VERSION 5.8 ;
BUSBITCHARS "[]" ;
DIVIDERCHAR "/" ;
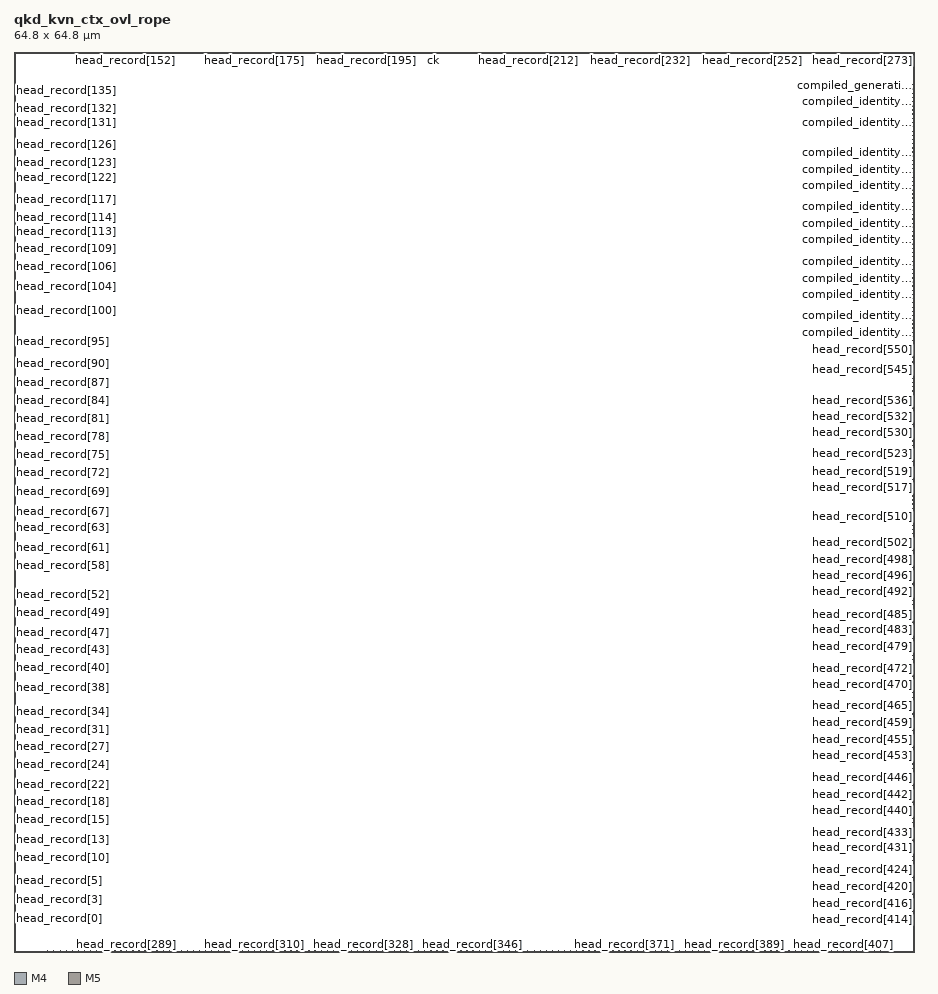
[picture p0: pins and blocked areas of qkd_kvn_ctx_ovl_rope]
MACRO qkd_kvn_ctx_ovl_rope
  CLASS BLOCK ;
  ORIGIN 0 0 ;
  SIZE 64.800000 BY 64.800000 ;
  SYMMETRY X Y ;
  PIN head_record[0]
    DIRECTION INPUT ;
    USE SIGNAL ;
    PORT
      LAYER M4 ;
      RECT 0.000000 2.400000 0.084000 2.424000 ;
    END
  END head_record[0]
  PIN head_record[1]
    DIRECTION INPUT ;
    USE SIGNAL ;
    PORT
      LAYER M4 ;
      RECT 0.000000 2.832000 0.084000 2.856000 ;
    END
  END head_record[1]
  PIN head_record[2]
    DIRECTION INPUT ;
    USE SIGNAL ;
    PORT
      LAYER M4 ;
      RECT 0.000000 3.312000 0.084000 3.336000 ;
    END
  END head_record[2]
  PIN head_record[3]
    DIRECTION INPUT ;
    USE SIGNAL ;
    PORT
      LAYER M4 ;
      RECT 0.000000 3.744000 0.084000 3.768000 ;
    END
  END head_record[3]
  PIN head_record[4]
    DIRECTION INPUT ;
    USE SIGNAL ;
    PORT
      LAYER M4 ;
      RECT 0.000000 4.176000 0.084000 4.200000 ;
    END
  END head_record[4]
  PIN head_record[5]
    DIRECTION INPUT ;
    USE SIGNAL ;
    PORT
      LAYER M4 ;
      RECT 0.000000 4.608000 0.084000 4.632000 ;
    END
  END head_record[5]
  PIN head_record[6]
    DIRECTION INPUT ;
    USE SIGNAL ;
    PORT
      LAYER M4 ;
      RECT 0.000000 5.040000 0.084000 5.064000 ;
    END
  END head_record[6]
  PIN head_record[7]
    DIRECTION INPUT ;
    USE SIGNAL ;
    PORT
      LAYER M4 ;
      RECT 0.000000 5.472000 0.084000 5.496000 ;
    END
  END head_record[7]
  PIN head_record[8]
    DIRECTION INPUT ;
    USE SIGNAL ;
    PORT
      LAYER M4 ;
      RECT 0.000000 5.904000 0.084000 5.928000 ;
    END
  END head_record[8]
  PIN head_record[9]
    DIRECTION INPUT ;
    USE SIGNAL ;
    PORT
      LAYER M4 ;
      RECT 0.000000 6.336000 0.084000 6.360000 ;
    END
  END head_record[9]
  PIN head_record[10]
    DIRECTION INPUT ;
    USE SIGNAL ;
    PORT
      LAYER M4 ;
      RECT 0.000000 6.768000 0.084000 6.792000 ;
    END
  END head_record[10]
  PIN head_record[11]
    DIRECTION INPUT ;
    USE SIGNAL ;
    PORT
      LAYER M4 ;
      RECT 0.000000 7.248000 0.084000 7.272000 ;
    END
  END head_record[11]
  PIN head_record[12]
    DIRECTION INPUT ;
    USE SIGNAL ;
    PORT
      LAYER M4 ;
      RECT 0.000000 7.680000 0.084000 7.704000 ;
    END
  END head_record[12]
  PIN head_record[13]
    DIRECTION INPUT ;
    USE SIGNAL ;
    PORT
      LAYER M4 ;
      RECT 0.000000 8.112000 0.084000 8.136000 ;
    END
  END head_record[13]
  PIN head_record[14]
    DIRECTION INPUT ;
    USE SIGNAL ;
    PORT
      LAYER M4 ;
      RECT 0.000000 8.544000 0.084000 8.568000 ;
    END
  END head_record[14]
  PIN head_record[15]
    DIRECTION INPUT ;
    USE SIGNAL ;
    PORT
      LAYER M4 ;
      RECT 0.000000 8.976000 0.084000 9.000000 ;
    END
  END head_record[15]
  PIN head_record[16]
    DIRECTION INPUT ;
    USE SIGNAL ;
    PORT
      LAYER M4 ;
      RECT 0.000000 9.408000 0.084000 9.432000 ;
    END
  END head_record[16]
  PIN head_record[17]
    DIRECTION INPUT ;
    USE SIGNAL ;
    PORT
      LAYER M4 ;
      RECT 0.000000 9.840000 0.084000 9.864000 ;
    END
  END head_record[17]
  PIN head_record[18]
    DIRECTION INPUT ;
    USE SIGNAL ;
    PORT
      LAYER M4 ;
      RECT 0.000000 10.272000 0.084000 10.296000 ;
    END
  END head_record[18]
  PIN head_record[19]
    DIRECTION INPUT ;
    USE SIGNAL ;
    PORT
      LAYER M4 ;
      RECT 0.000000 10.752000 0.084000 10.776000 ;
    END
  END head_record[19]
  PIN head_record[20]
    DIRECTION INPUT ;
    USE SIGNAL ;
    PORT
      LAYER M4 ;
      RECT 0.000000 11.184000 0.084000 11.208000 ;
    END
  END head_record[20]
  PIN head_record[21]
    DIRECTION INPUT ;
    USE SIGNAL ;
    PORT
      LAYER M4 ;
      RECT 0.000000 11.616000 0.084000 11.640000 ;
    END
  END head_record[21]
  PIN head_record[22]
    DIRECTION INPUT ;
    USE SIGNAL ;
    PORT
      LAYER M4 ;
      RECT 0.000000 12.048000 0.084000 12.072000 ;
    END
  END head_record[22]
  PIN head_record[23]
    DIRECTION INPUT ;
    USE SIGNAL ;
    PORT
      LAYER M4 ;
      RECT 0.000000 12.480000 0.084000 12.504000 ;
    END
  END head_record[23]
  PIN head_record[24]
    DIRECTION INPUT ;
    USE SIGNAL ;
    PORT
      LAYER M4 ;
      RECT 0.000000 12.912000 0.084000 12.936000 ;
    END
  END head_record[24]
  PIN head_record[25]
    DIRECTION INPUT ;
    USE SIGNAL ;
    PORT
      LAYER M4 ;
      RECT 0.000000 13.344000 0.084000 13.368000 ;
    END
  END head_record[25]
  PIN head_record[26]
    DIRECTION INPUT ;
    USE SIGNAL ;
    PORT
      LAYER M4 ;
      RECT 0.000000 13.776000 0.084000 13.800000 ;
    END
  END head_record[26]
  PIN head_record[27]
    DIRECTION INPUT ;
    USE SIGNAL ;
    PORT
      LAYER M4 ;
      RECT 0.000000 14.208000 0.084000 14.232000 ;
    END
  END head_record[27]
  PIN head_record[28]
    DIRECTION INPUT ;
    USE SIGNAL ;
    PORT
      LAYER M4 ;
      RECT 0.000000 14.688000 0.084000 14.712000 ;
    END
  END head_record[28]
  PIN head_record[29]
    DIRECTION INPUT ;
    USE SIGNAL ;
    PORT
      LAYER M4 ;
      RECT 0.000000 15.120000 0.084000 15.144000 ;
    END
  END head_record[29]
  PIN head_record[30]
    DIRECTION INPUT ;
    USE SIGNAL ;
    PORT
      LAYER M4 ;
      RECT 0.000000 15.552000 0.084000 15.576000 ;
    END
  END head_record[30]
  PIN head_record[31]
    DIRECTION INPUT ;
    USE SIGNAL ;
    PORT
      LAYER M4 ;
      RECT 0.000000 15.984000 0.084000 16.008000 ;
    END
  END head_record[31]
  PIN head_record[32]
    DIRECTION INPUT ;
    USE SIGNAL ;
    PORT
      LAYER M4 ;
      RECT 0.000000 16.416000 0.084000 16.440000 ;
    END
  END head_record[32]
  PIN head_record[33]
    DIRECTION INPUT ;
    USE SIGNAL ;
    PORT
      LAYER M4 ;
      RECT 0.000000 16.848000 0.084000 16.872000 ;
    END
  END head_record[33]
  PIN head_record[34]
    DIRECTION INPUT ;
    USE SIGNAL ;
    PORT
      LAYER M4 ;
      RECT 0.000000 17.280000 0.084000 17.304000 ;
    END
  END head_record[34]
  PIN head_record[35]
    DIRECTION INPUT ;
    USE SIGNAL ;
    PORT
      LAYER M4 ;
      RECT 0.000000 17.712000 0.084000 17.736000 ;
    END
  END head_record[35]
  PIN head_record[36]
    DIRECTION INPUT ;
    USE SIGNAL ;
    PORT
      LAYER M4 ;
      RECT 0.000000 18.144000 0.084000 18.168000 ;
    END
  END head_record[36]
  PIN head_record[37]
    DIRECTION INPUT ;
    USE SIGNAL ;
    PORT
      LAYER M4 ;
      RECT 0.000000 18.624000 0.084000 18.648000 ;
    END
  END head_record[37]
  PIN head_record[38]
    DIRECTION INPUT ;
    USE SIGNAL ;
    PORT
      LAYER M4 ;
      RECT 0.000000 19.056000 0.084000 19.080000 ;
    END
  END head_record[38]
  PIN head_record[39]
    DIRECTION INPUT ;
    USE SIGNAL ;
    PORT
      LAYER M4 ;
      RECT 0.000000 19.488000 0.084000 19.512000 ;
    END
  END head_record[39]
  PIN head_record[40]
    DIRECTION INPUT ;
    USE SIGNAL ;
    PORT
      LAYER M4 ;
      RECT 0.000000 19.920000 0.084000 19.944000 ;
    END
  END head_record[40]
  PIN head_record[41]
    DIRECTION INPUT ;
    USE SIGNAL ;
    PORT
      LAYER M4 ;
      RECT 0.000000 20.352000 0.084000 20.376000 ;
    END
  END head_record[41]
  PIN head_record[42]
    DIRECTION INPUT ;
    USE SIGNAL ;
    PORT
      LAYER M4 ;
      RECT 0.000000 20.784000 0.084000 20.808000 ;
    END
  END head_record[42]
  PIN head_record[43]
    DIRECTION INPUT ;
    USE SIGNAL ;
    PORT
      LAYER M4 ;
      RECT 0.000000 21.216000 0.084000 21.240000 ;
    END
  END head_record[43]
  PIN head_record[44]
    DIRECTION INPUT ;
    USE SIGNAL ;
    PORT
      LAYER M4 ;
      RECT 0.000000 21.648000 0.084000 21.672000 ;
    END
  END head_record[44]
  PIN head_record[45]
    DIRECTION INPUT ;
    USE SIGNAL ;
    PORT
      LAYER M4 ;
      RECT 0.000000 22.128000 0.084000 22.152000 ;
    END
  END head_record[45]
  PIN head_record[46]
    DIRECTION INPUT ;
    USE SIGNAL ;
    PORT
      LAYER M4 ;
      RECT 0.000000 22.560000 0.084000 22.584000 ;
    END
  END head_record[46]
  PIN head_record[47]
    DIRECTION INPUT ;
    USE SIGNAL ;
    PORT
      LAYER M4 ;
      RECT 0.000000 22.992000 0.084000 23.016000 ;
    END
  END head_record[47]
  PIN head_record[48]
    DIRECTION INPUT ;
    USE SIGNAL ;
    PORT
      LAYER M4 ;
      RECT 0.000000 23.424000 0.084000 23.448000 ;
    END
  END head_record[48]
  PIN head_record[49]
    DIRECTION INPUT ;
    USE SIGNAL ;
    PORT
      LAYER M4 ;
      RECT 0.000000 23.856000 0.084000 23.880000 ;
    END
  END head_record[49]
  PIN head_record[50]
    DIRECTION INPUT ;
    USE SIGNAL ;
    PORT
      LAYER M4 ;
      RECT 0.000000 24.288000 0.084000 24.312000 ;
    END
  END head_record[50]
  PIN head_record[51]
    DIRECTION INPUT ;
    USE SIGNAL ;
    PORT
      LAYER M4 ;
      RECT 0.000000 24.720000 0.084000 24.744000 ;
    END
  END head_record[51]
  PIN head_record[52]
    DIRECTION INPUT ;
    USE SIGNAL ;
    PORT
      LAYER M4 ;
      RECT 0.000000 25.152000 0.084000 25.176000 ;
    END
  END head_record[52]
  PIN head_record[53]
    DIRECTION INPUT ;
    USE SIGNAL ;
    PORT
      LAYER M4 ;
      RECT 0.000000 25.584000 0.084000 25.608000 ;
    END
  END head_record[53]
  PIN head_record[54]
    DIRECTION INPUT ;
    USE SIGNAL ;
    PORT
      LAYER M4 ;
      RECT 0.000000 26.064000 0.084000 26.088000 ;
    END
  END head_record[54]
  PIN head_record[55]
    DIRECTION INPUT ;
    USE SIGNAL ;
    PORT
      LAYER M4 ;
      RECT 0.000000 26.496000 0.084000 26.520000 ;
    END
  END head_record[55]
  PIN head_record[56]
    DIRECTION INPUT ;
    USE SIGNAL ;
    PORT
      LAYER M4 ;
      RECT 0.000000 26.928000 0.084000 26.952000 ;
    END
  END head_record[56]
  PIN head_record[57]
    DIRECTION INPUT ;
    USE SIGNAL ;
    PORT
      LAYER M4 ;
      RECT 0.000000 27.360000 0.084000 27.384000 ;
    END
  END head_record[57]
  PIN head_record[58]
    DIRECTION INPUT ;
    USE SIGNAL ;
    PORT
      LAYER M4 ;
      RECT 0.000000 27.792000 0.084000 27.816000 ;
    END
  END head_record[58]
  PIN head_record[59]
    DIRECTION INPUT ;
    USE SIGNAL ;
    PORT
      LAYER M4 ;
      RECT 0.000000 28.224000 0.084000 28.248000 ;
    END
  END head_record[59]
  PIN head_record[60]
    DIRECTION INPUT ;
    USE SIGNAL ;
    PORT
      LAYER M4 ;
      RECT 0.000000 28.656000 0.084000 28.680000 ;
    END
  END head_record[60]
  PIN head_record[61]
    DIRECTION INPUT ;
    USE SIGNAL ;
    PORT
      LAYER M4 ;
      RECT 0.000000 29.088000 0.084000 29.112000 ;
    END
  END head_record[61]
  PIN head_record[62]
    DIRECTION INPUT ;
    USE SIGNAL ;
    PORT
      LAYER M4 ;
      RECT 0.000000 29.520000 0.084000 29.544000 ;
    END
  END head_record[62]
  PIN head_record[63]
    DIRECTION INPUT ;
    USE SIGNAL ;
    PORT
      LAYER M4 ;
      RECT 0.000000 30.000000 0.084000 30.024000 ;
    END
  END head_record[63]
  PIN head_record[64]
    DIRECTION INPUT ;
    USE SIGNAL ;
    PORT
      LAYER M4 ;
      RECT 0.000000 30.432000 0.084000 30.456000 ;
    END
  END head_record[64]
  PIN head_record[65]
    DIRECTION INPUT ;
    USE SIGNAL ;
    PORT
      LAYER M4 ;
      RECT 0.000000 30.864000 0.084000 30.888000 ;
    END
  END head_record[65]
  PIN head_record[66]
    DIRECTION INPUT ;
    USE SIGNAL ;
    PORT
      LAYER M4 ;
      RECT 0.000000 31.296000 0.084000 31.320000 ;
    END
  END head_record[66]
  PIN head_record[67]
    DIRECTION INPUT ;
    USE SIGNAL ;
    PORT
      LAYER M4 ;
      RECT 0.000000 31.728000 0.084000 31.752000 ;
    END
  END head_record[67]
  PIN head_record[68]
    DIRECTION INPUT ;
    USE SIGNAL ;
    PORT
      LAYER M4 ;
      RECT 0.000000 32.160000 0.084000 32.184000 ;
    END
  END head_record[68]
  PIN head_record[69]
    DIRECTION INPUT ;
    USE SIGNAL ;
    PORT
      LAYER M4 ;
      RECT 0.000000 32.592000 0.084000 32.616000 ;
    END
  END head_record[69]
  PIN head_record[70]
    DIRECTION INPUT ;
    USE SIGNAL ;
    PORT
      LAYER M4 ;
      RECT 0.000000 33.024000 0.084000 33.048000 ;
    END
  END head_record[70]
  PIN head_record[71]
    DIRECTION INPUT ;
    USE SIGNAL ;
    PORT
      LAYER M4 ;
      RECT 0.000000 33.504000 0.084000 33.528000 ;
    END
  END head_record[71]
  PIN head_record[72]
    DIRECTION INPUT ;
    USE SIGNAL ;
    PORT
      LAYER M4 ;
      RECT 0.000000 33.936000 0.084000 33.960000 ;
    END
  END head_record[72]
  PIN head_record[73]
    DIRECTION INPUT ;
    USE SIGNAL ;
    PORT
      LAYER M4 ;
      RECT 0.000000 34.368000 0.084000 34.392000 ;
    END
  END head_record[73]
  PIN head_record[74]
    DIRECTION INPUT ;
    USE SIGNAL ;
    PORT
      LAYER M4 ;
      RECT 0.000000 34.800000 0.084000 34.824000 ;
    END
  END head_record[74]
  PIN head_record[75]
    DIRECTION INPUT ;
    USE SIGNAL ;
    PORT
      LAYER M4 ;
      RECT 0.000000 35.232000 0.084000 35.256000 ;
    END
  END head_record[75]
  PIN head_record[76]
    DIRECTION INPUT ;
    USE SIGNAL ;
    PORT
      LAYER M4 ;
      RECT 0.000000 35.664000 0.084000 35.688000 ;
    END
  END head_record[76]
  PIN head_record[77]
    DIRECTION INPUT ;
    USE SIGNAL ;
    PORT
      LAYER M4 ;
      RECT 0.000000 36.096000 0.084000 36.120000 ;
    END
  END head_record[77]
  PIN head_record[78]
    DIRECTION INPUT ;
    USE SIGNAL ;
    PORT
      LAYER M4 ;
      RECT 0.000000 36.528000 0.084000 36.552000 ;
    END
  END head_record[78]
  PIN head_record[79]
    DIRECTION INPUT ;
    USE SIGNAL ;
    PORT
      LAYER M4 ;
      RECT 0.000000 36.960000 0.084000 36.984000 ;
    END
  END head_record[79]
  PIN head_record[80]
    DIRECTION INPUT ;
    USE SIGNAL ;
    PORT
      LAYER M4 ;
      RECT 0.000000 37.440000 0.084000 37.464000 ;
    END
  END head_record[80]
  PIN head_record[81]
    DIRECTION INPUT ;
    USE SIGNAL ;
    PORT
      LAYER M4 ;
      RECT 0.000000 37.872000 0.084000 37.896000 ;
    END
  END head_record[81]
  PIN head_record[82]
    DIRECTION INPUT ;
    USE SIGNAL ;
    PORT
      LAYER M4 ;
      RECT 0.000000 38.304000 0.084000 38.328000 ;
    END
  END head_record[82]
  PIN head_record[83]
    DIRECTION INPUT ;
    USE SIGNAL ;
    PORT
      LAYER M4 ;
      RECT 0.000000 38.736000 0.084000 38.760000 ;
    END
  END head_record[83]
  PIN head_record[84]
    DIRECTION INPUT ;
    USE SIGNAL ;
    PORT
      LAYER M4 ;
      RECT 0.000000 39.168000 0.084000 39.192000 ;
    END
  END head_record[84]
  PIN head_record[85]
    DIRECTION INPUT ;
    USE SIGNAL ;
    PORT
      LAYER M4 ;
      RECT 0.000000 39.600000 0.084000 39.624000 ;
    END
  END head_record[85]
  PIN head_record[86]
    DIRECTION INPUT ;
    USE SIGNAL ;
    PORT
      LAYER M4 ;
      RECT 0.000000 40.032000 0.084000 40.056000 ;
    END
  END head_record[86]
  PIN head_record[87]
    DIRECTION INPUT ;
    USE SIGNAL ;
    PORT
      LAYER M4 ;
      RECT 0.000000 40.464000 0.084000 40.488000 ;
    END
  END head_record[87]
  PIN head_record[88]
    DIRECTION INPUT ;
    USE SIGNAL ;
    PORT
      LAYER M4 ;
      RECT 0.000000 40.944000 0.084000 40.968000 ;
    END
  END head_record[88]
  PIN head_record[89]
    DIRECTION INPUT ;
    USE SIGNAL ;
    PORT
      LAYER M4 ;
      RECT 0.000000 41.376000 0.084000 41.400000 ;
    END
  END head_record[89]
  PIN head_record[90]
    DIRECTION INPUT ;
    USE SIGNAL ;
    PORT
      LAYER M4 ;
      RECT 0.000000 41.808000 0.084000 41.832000 ;
    END
  END head_record[90]
  PIN head_record[91]
    DIRECTION INPUT ;
    USE SIGNAL ;
    PORT
      LAYER M4 ;
      RECT 0.000000 42.240000 0.084000 42.264000 ;
    END
  END head_record[91]
  PIN head_record[92]
    DIRECTION INPUT ;
    USE SIGNAL ;
    PORT
      LAYER M4 ;
      RECT 0.000000 42.672000 0.084000 42.696000 ;
    END
  END head_record[92]
  PIN head_record[93]
    DIRECTION INPUT ;
    USE SIGNAL ;
    PORT
      LAYER M4 ;
      RECT 0.000000 43.104000 0.084000 43.128000 ;
    END
  END head_record[93]
  PIN head_record[94]
    DIRECTION INPUT ;
    USE SIGNAL ;
    PORT
      LAYER M4 ;
      RECT 0.000000 43.536000 0.084000 43.560000 ;
    END
  END head_record[94]
  PIN head_record[95]
    DIRECTION INPUT ;
    USE SIGNAL ;
    PORT
      LAYER M4 ;
      RECT 0.000000 43.968000 0.084000 43.992000 ;
    END
  END head_record[95]
  PIN head_record[96]
    DIRECTION INPUT ;
    USE SIGNAL ;
    PORT
      LAYER M4 ;
      RECT 0.000000 44.400000 0.084000 44.424000 ;
    END
  END head_record[96]
  PIN head_record[97]
    DIRECTION INPUT ;
    USE SIGNAL ;
    PORT
      LAYER M4 ;
      RECT 0.000000 44.880000 0.084000 44.904000 ;
    END
  END head_record[97]
  PIN head_record[98]
    DIRECTION INPUT ;
    USE SIGNAL ;
    PORT
      LAYER M4 ;
      RECT 0.000000 45.312000 0.084000 45.336000 ;
    END
  END head_record[98]
  PIN head_record[99]
    DIRECTION INPUT ;
    USE SIGNAL ;
    PORT
      LAYER M4 ;
      RECT 0.000000 45.744000 0.084000 45.768000 ;
    END
  END head_record[99]
  PIN head_record[100]
    DIRECTION INPUT ;
    USE SIGNAL ;
    PORT
      LAYER M4 ;
      RECT 0.000000 46.176000 0.084000 46.200000 ;
    END
  END head_record[100]
  PIN head_record[101]
    DIRECTION INPUT ;
    USE SIGNAL ;
    PORT
      LAYER M4 ;
      RECT 0.000000 46.608000 0.084000 46.632000 ;
    END
  END head_record[101]
  PIN head_record[102]
    DIRECTION INPUT ;
    USE SIGNAL ;
    PORT
      LAYER M4 ;
      RECT 0.000000 47.040000 0.084000 47.064000 ;
    END
  END head_record[102]
  PIN head_record[103]
    DIRECTION INPUT ;
    USE SIGNAL ;
    PORT
      LAYER M4 ;
      RECT 0.000000 47.472000 0.084000 47.496000 ;
    END
  END head_record[103]
  PIN head_record[104]
    DIRECTION INPUT ;
    USE SIGNAL ;
    PORT
      LAYER M4 ;
      RECT 0.000000 47.904000 0.084000 47.928000 ;
    END
  END head_record[104]
  PIN head_record[105]
    DIRECTION INPUT ;
    USE SIGNAL ;
    PORT
      LAYER M4 ;
      RECT 0.000000 48.336000 0.084000 48.360000 ;
    END
  END head_record[105]
  PIN head_record[106]
    DIRECTION INPUT ;
    USE SIGNAL ;
    PORT
      LAYER M4 ;
      RECT 0.000000 48.816000 0.084000 48.840000 ;
    END
  END head_record[106]
  PIN head_record[107]
    DIRECTION INPUT ;
    USE SIGNAL ;
    PORT
      LAYER M4 ;
      RECT 0.000000 49.248000 0.084000 49.272000 ;
    END
  END head_record[107]
  PIN head_record[108]
    DIRECTION INPUT ;
    USE SIGNAL ;
    PORT
      LAYER M4 ;
      RECT 0.000000 49.680000 0.084000 49.704000 ;
    END
  END head_record[108]
  PIN head_record[109]
    DIRECTION INPUT ;
    USE SIGNAL ;
    PORT
      LAYER M4 ;
      RECT 0.000000 50.112000 0.084000 50.136000 ;
    END
  END head_record[109]
  PIN head_record[110]
    DIRECTION INPUT ;
    USE SIGNAL ;
    PORT
      LAYER M4 ;
      RECT 0.000000 50.544000 0.084000 50.568000 ;
    END
  END head_record[110]
  PIN head_record[111]
    DIRECTION INPUT ;
    USE SIGNAL ;
    PORT
      LAYER M4 ;
      RECT 0.000000 50.976000 0.084000 51.000000 ;
    END
  END head_record[111]
  PIN head_record[112]
    DIRECTION INPUT ;
    USE SIGNAL ;
    PORT
      LAYER M4 ;
      RECT 0.000000 51.408000 0.084000 51.432000 ;
    END
  END head_record[112]
  PIN head_record[113]
    DIRECTION INPUT ;
    USE SIGNAL ;
    PORT
      LAYER M4 ;
      RECT 0.000000 51.840000 0.084000 51.864000 ;
    END
  END head_record[113]
  PIN head_record[114]
    DIRECTION INPUT ;
    USE SIGNAL ;
    PORT
      LAYER M4 ;
      RECT 0.000000 52.320000 0.084000 52.344000 ;
    END
  END head_record[114]
  PIN head_record[115]
    DIRECTION INPUT ;
    USE SIGNAL ;
    PORT
      LAYER M4 ;
      RECT 0.000000 52.752000 0.084000 52.776000 ;
    END
  END head_record[115]
  PIN head_record[116]
    DIRECTION INPUT ;
    USE SIGNAL ;
    PORT
      LAYER M4 ;
      RECT 0.000000 53.184000 0.084000 53.208000 ;
    END
  END head_record[116]
  PIN head_record[117]
    DIRECTION INPUT ;
    USE SIGNAL ;
    PORT
      LAYER M4 ;
      RECT 0.000000 53.616000 0.084000 53.640000 ;
    END
  END head_record[117]
  PIN head_record[118]
    DIRECTION INPUT ;
    USE SIGNAL ;
    PORT
      LAYER M4 ;
      RECT 0.000000 54.048000 0.084000 54.072000 ;
    END
  END head_record[118]
  PIN head_record[119]
    DIRECTION INPUT ;
    USE SIGNAL ;
    PORT
      LAYER M4 ;
      RECT 0.000000 54.480000 0.084000 54.504000 ;
    END
  END head_record[119]
  PIN head_record[120]
    DIRECTION INPUT ;
    USE SIGNAL ;
    PORT
      LAYER M4 ;
      RECT 0.000000 54.912000 0.084000 54.936000 ;
    END
  END head_record[120]
  PIN head_record[121]
    DIRECTION INPUT ;
    USE SIGNAL ;
    PORT
      LAYER M4 ;
      RECT 0.000000 55.344000 0.084000 55.368000 ;
    END
  END head_record[121]
  PIN head_record[122]
    DIRECTION INPUT ;
    USE SIGNAL ;
    PORT
      LAYER M4 ;
      RECT 0.000000 55.776000 0.084000 55.800000 ;
    END
  END head_record[122]
  PIN head_record[123]
    DIRECTION INPUT ;
    USE SIGNAL ;
    PORT
      LAYER M4 ;
      RECT 0.000000 56.256000 0.084000 56.280000 ;
    END
  END head_record[123]
  PIN head_record[124]
    DIRECTION INPUT ;
    USE SIGNAL ;
    PORT
      LAYER M4 ;
      RECT 0.000000 56.688000 0.084000 56.712000 ;
    END
  END head_record[124]
  PIN head_record[125]
    DIRECTION INPUT ;
    USE SIGNAL ;
    PORT
      LAYER M4 ;
      RECT 0.000000 57.120000 0.084000 57.144000 ;
    END
  END head_record[125]
  PIN head_record[126]
    DIRECTION INPUT ;
    USE SIGNAL ;
    PORT
      LAYER M4 ;
      RECT 0.000000 57.552000 0.084000 57.576000 ;
    END
  END head_record[126]
  PIN head_record[127]
    DIRECTION INPUT ;
    USE SIGNAL ;
    PORT
      LAYER M4 ;
      RECT 0.000000 57.984000 0.084000 58.008000 ;
    END
  END head_record[127]
  PIN head_record[128]
    DIRECTION INPUT ;
    USE SIGNAL ;
    PORT
      LAYER M4 ;
      RECT 0.000000 58.416000 0.084000 58.440000 ;
    END
  END head_record[128]
  PIN head_record[129]
    DIRECTION INPUT ;
    USE SIGNAL ;
    PORT
      LAYER M4 ;
      RECT 0.000000 58.848000 0.084000 58.872000 ;
    END
  END head_record[129]
  PIN head_record[130]
    DIRECTION INPUT ;
    USE SIGNAL ;
    PORT
      LAYER M4 ;
      RECT 0.000000 59.280000 0.084000 59.304000 ;
    END
  END head_record[130]
  PIN head_record[131]
    DIRECTION INPUT ;
    USE SIGNAL ;
    PORT
      LAYER M4 ;
      RECT 0.000000 59.712000 0.084000 59.736000 ;
    END
  END head_record[131]
  PIN head_record[132]
    DIRECTION INPUT ;
    USE SIGNAL ;
    PORT
      LAYER M4 ;
      RECT 0.000000 60.192000 0.084000 60.216000 ;
    END
  END head_record[132]
  PIN head_record[133]
    DIRECTION INPUT ;
    USE SIGNAL ;
    PORT
      LAYER M4 ;
      RECT 0.000000 60.624000 0.084000 60.648000 ;
    END
  END head_record[133]
  PIN head_record[134]
    DIRECTION INPUT ;
    USE SIGNAL ;
    PORT
      LAYER M4 ;
      RECT 0.000000 61.056000 0.084000 61.080000 ;
    END
  END head_record[134]
  PIN head_record[135]
    DIRECTION INPUT ;
    USE SIGNAL ;
    PORT
      LAYER M4 ;
      RECT 0.000000 61.488000 0.084000 61.512000 ;
    END
  END head_record[135]
  PIN head_record[136]
    DIRECTION INPUT ;
    USE SIGNAL ;
    PORT
      LAYER M4 ;
      RECT 0.000000 61.920000 0.084000 61.944000 ;
    END
  END head_record[136]
  PIN head_record[137]
    DIRECTION INPUT ;
    USE SIGNAL ;
    PORT
      LAYER M4 ;
      RECT 0.000000 62.352000 0.084000 62.376000 ;
    END
  END head_record[137]
  PIN head_record[138]
    DIRECTION INPUT ;
    USE SIGNAL ;
    PORT
      LAYER M5 ;
      RECT 2.400000 64.716000 2.424000 64.800000 ;
    END
  END head_record[138]
  PIN head_record[139]
    DIRECTION INPUT ;
    USE SIGNAL ;
    PORT
      LAYER M5 ;
      RECT 2.784000 64.716000 2.808000 64.800000 ;
    END
  END head_record[139]
  PIN head_record[140]
    DIRECTION INPUT ;
    USE SIGNAL ;
    PORT
      LAYER M5 ;
      RECT 3.216000 64.716000 3.240000 64.800000 ;
    END
  END head_record[140]
  PIN head_record[141]
    DIRECTION INPUT ;
    USE SIGNAL ;
    PORT
      LAYER M5 ;
      RECT 3.600000 64.716000 3.624000 64.800000 ;
    END
  END head_record[141]
  PIN head_record[142]
    DIRECTION INPUT ;
    USE SIGNAL ;
    PORT
      LAYER M5 ;
      RECT 3.984000 64.716000 4.008000 64.800000 ;
    END
  END head_record[142]
  PIN head_record[143]
    DIRECTION INPUT ;
    USE SIGNAL ;
    PORT
      LAYER M5 ;
      RECT 4.416000 64.716000 4.440000 64.800000 ;
    END
  END head_record[143]
  PIN head_record[144]
    DIRECTION INPUT ;
    USE SIGNAL ;
    PORT
      LAYER M5 ;
      RECT 4.800000 64.716000 4.824000 64.800000 ;
    END
  END head_record[144]
  PIN head_record[145]
    DIRECTION INPUT ;
    USE SIGNAL ;
    PORT
      LAYER M5 ;
      RECT 5.232000 64.716000 5.256000 64.800000 ;
    END
  END head_record[145]
  PIN head_record[146]
    DIRECTION INPUT ;
    USE SIGNAL ;
    PORT
      LAYER M5 ;
      RECT 5.616000 64.716000 5.640000 64.800000 ;
    END
  END head_record[146]
  PIN head_record[147]
    DIRECTION INPUT ;
    USE SIGNAL ;
    PORT
      LAYER M5 ;
      RECT 6.000000 64.716000 6.024000 64.800000 ;
    END
  END head_record[147]
  PIN head_record[148]
    DIRECTION INPUT ;
    USE SIGNAL ;
    PORT
      LAYER M5 ;
      RECT 6.432000 64.716000 6.456000 64.800000 ;
    END
  END head_record[148]
  PIN head_record[149]
    DIRECTION INPUT ;
    USE SIGNAL ;
    PORT
      LAYER M5 ;
      RECT 6.816000 64.716000 6.840000 64.800000 ;
    END
  END head_record[149]
  PIN head_record[150]
    DIRECTION INPUT ;
    USE SIGNAL ;
    PORT
      LAYER M5 ;
      RECT 7.248000 64.716000 7.272000 64.800000 ;
    END
  END head_record[150]
  PIN head_record[151]
    DIRECTION INPUT ;
    USE SIGNAL ;
    PORT
      LAYER M5 ;
      RECT 7.632000 64.716000 7.656000 64.800000 ;
    END
  END head_record[151]
  PIN head_record[152]
    DIRECTION INPUT ;
    USE SIGNAL ;
    PORT
      LAYER M5 ;
      RECT 8.016000 64.716000 8.040000 64.800000 ;
    END
  END head_record[152]
  PIN head_record[153]
    DIRECTION INPUT ;
    USE SIGNAL ;
    PORT
      LAYER M5 ;
      RECT 8.448000 64.716000 8.472000 64.800000 ;
    END
  END head_record[153]
  PIN head_record[154]
    DIRECTION INPUT ;
    USE SIGNAL ;
    PORT
      LAYER M5 ;
      RECT 8.832000 64.716000 8.856000 64.800000 ;
    END
  END head_record[154]
  PIN head_record[155]
    DIRECTION INPUT ;
    USE SIGNAL ;
    PORT
      LAYER M5 ;
      RECT 9.264000 64.716000 9.288000 64.800000 ;
    END
  END head_record[155]
  PIN head_record[156]
    DIRECTION INPUT ;
    USE SIGNAL ;
    PORT
      LAYER M5 ;
      RECT 9.648000 64.716000 9.672000 64.800000 ;
    END
  END head_record[156]
  PIN head_record[157]
    DIRECTION INPUT ;
    USE SIGNAL ;
    PORT
      LAYER M5 ;
      RECT 10.032000 64.716000 10.056000 64.800000 ;
    END
  END head_record[157]
  PIN head_record[158]
    DIRECTION INPUT ;
    USE SIGNAL ;
    PORT
      LAYER M5 ;
      RECT 10.464000 64.716000 10.488000 64.800000 ;
    END
  END head_record[158]
  PIN head_record[159]
    DIRECTION INPUT ;
    USE SIGNAL ;
    PORT
      LAYER M5 ;
      RECT 10.848000 64.716000 10.872000 64.800000 ;
    END
  END head_record[159]
  PIN head_record[160]
    DIRECTION INPUT ;
    USE SIGNAL ;
    PORT
      LAYER M5 ;
      RECT 11.232000 64.716000 11.256000 64.800000 ;
    END
  END head_record[160]
  PIN head_record[161]
    DIRECTION INPUT ;
    USE SIGNAL ;
    PORT
      LAYER M5 ;
      RECT 11.664000 64.716000 11.688000 64.800000 ;
    END
  END head_record[161]
  PIN head_record[162]
    DIRECTION INPUT ;
    USE SIGNAL ;
    PORT
      LAYER M5 ;
      RECT 12.048000 64.716000 12.072000 64.800000 ;
    END
  END head_record[162]
  PIN head_record[163]
    DIRECTION INPUT ;
    USE SIGNAL ;
    PORT
      LAYER M5 ;
      RECT 12.480000 64.716000 12.504000 64.800000 ;
    END
  END head_record[163]
  PIN head_record[164]
    DIRECTION INPUT ;
    USE SIGNAL ;
    PORT
      LAYER M5 ;
      RECT 12.864000 64.716000 12.888000 64.800000 ;
    END
  END head_record[164]
  PIN head_record[165]
    DIRECTION INPUT ;
    USE SIGNAL ;
    PORT
      LAYER M5 ;
      RECT 13.248000 64.716000 13.272000 64.800000 ;
    END
  END head_record[165]
  PIN head_record[166]
    DIRECTION INPUT ;
    USE SIGNAL ;
    PORT
      LAYER M5 ;
      RECT 13.680000 64.716000 13.704000 64.800000 ;
    END
  END head_record[166]
  PIN head_record[167]
    DIRECTION INPUT ;
    USE SIGNAL ;
    PORT
      LAYER M5 ;
      RECT 14.064000 64.716000 14.088000 64.800000 ;
    END
  END head_record[167]
  PIN head_record[168]
    DIRECTION INPUT ;
    USE SIGNAL ;
    PORT
      LAYER M5 ;
      RECT 14.496000 64.716000 14.520000 64.800000 ;
    END
  END head_record[168]
  PIN head_record[169]
    DIRECTION INPUT ;
    USE SIGNAL ;
    PORT
      LAYER M5 ;
      RECT 14.880000 64.716000 14.904000 64.800000 ;
    END
  END head_record[169]
  PIN head_record[170]
    DIRECTION INPUT ;
    USE SIGNAL ;
    PORT
      LAYER M5 ;
      RECT 15.264000 64.716000 15.288000 64.800000 ;
    END
  END head_record[170]
  PIN head_record[171]
    DIRECTION INPUT ;
    USE SIGNAL ;
    PORT
      LAYER M5 ;
      RECT 15.696000 64.716000 15.720000 64.800000 ;
    END
  END head_record[171]
  PIN head_record[172]
    DIRECTION INPUT ;
    USE SIGNAL ;
    PORT
      LAYER M5 ;
      RECT 16.080000 64.716000 16.104000 64.800000 ;
    END
  END head_record[172]
  PIN head_record[173]
    DIRECTION INPUT ;
    USE SIGNAL ;
    PORT
      LAYER M5 ;
      RECT 16.464000 64.716000 16.488000 64.800000 ;
    END
  END head_record[173]
  PIN head_record[174]
    DIRECTION INPUT ;
    USE SIGNAL ;
    PORT
      LAYER M5 ;
      RECT 16.896000 64.716000 16.920000 64.800000 ;
    END
  END head_record[174]
  PIN head_record[175]
    DIRECTION INPUT ;
    USE SIGNAL ;
    PORT
      LAYER M5 ;
      RECT 17.280000 64.716000 17.304000 64.800000 ;
    END
  END head_record[175]
  PIN head_record[176]
    DIRECTION INPUT ;
    USE SIGNAL ;
    PORT
      LAYER M5 ;
      RECT 17.712000 64.716000 17.736000 64.800000 ;
    END
  END head_record[176]
  PIN head_record[177]
    DIRECTION INPUT ;
    USE SIGNAL ;
    PORT
      LAYER M5 ;
      RECT 18.096000 64.716000 18.120000 64.800000 ;
    END
  END head_record[177]
  PIN head_record[178]
    DIRECTION INPUT ;
    USE SIGNAL ;
    PORT
      LAYER M5 ;
      RECT 18.480000 64.716000 18.504000 64.800000 ;
    END
  END head_record[178]
  PIN head_record[179]
    DIRECTION INPUT ;
    USE SIGNAL ;
    PORT
      LAYER M5 ;
      RECT 18.912000 64.716000 18.936000 64.800000 ;
    END
  END head_record[179]
  PIN head_record[180]
    DIRECTION INPUT ;
    USE SIGNAL ;
    PORT
      LAYER M5 ;
      RECT 19.296000 64.716000 19.320000 64.800000 ;
    END
  END head_record[180]
  PIN head_record[181]
    DIRECTION INPUT ;
    USE SIGNAL ;
    PORT
      LAYER M5 ;
      RECT 19.728000 64.716000 19.752000 64.800000 ;
    END
  END head_record[181]
  PIN head_record[182]
    DIRECTION INPUT ;
    USE SIGNAL ;
    PORT
      LAYER M5 ;
      RECT 20.112000 64.716000 20.136000 64.800000 ;
    END
  END head_record[182]
  PIN head_record[183]
    DIRECTION INPUT ;
    USE SIGNAL ;
    PORT
      LAYER M5 ;
      RECT 20.496000 64.716000 20.520000 64.800000 ;
    END
  END head_record[183]
  PIN head_record[184]
    DIRECTION INPUT ;
    USE SIGNAL ;
    PORT
      LAYER M5 ;
      RECT 20.928000 64.716000 20.952000 64.800000 ;
    END
  END head_record[184]
  PIN head_record[185]
    DIRECTION INPUT ;
    USE SIGNAL ;
    PORT
      LAYER M5 ;
      RECT 21.312000 64.716000 21.336000 64.800000 ;
    END
  END head_record[185]
  PIN head_record[186]
    DIRECTION INPUT ;
    USE SIGNAL ;
    PORT
      LAYER M5 ;
      RECT 21.744000 64.716000 21.768000 64.800000 ;
    END
  END head_record[186]
  PIN head_record[187]
    DIRECTION INPUT ;
    USE SIGNAL ;
    PORT
      LAYER M5 ;
      RECT 22.128000 64.716000 22.152000 64.800000 ;
    END
  END head_record[187]
  PIN head_record[188]
    DIRECTION INPUT ;
    USE SIGNAL ;
    PORT
      LAYER M5 ;
      RECT 22.512000 64.716000 22.536000 64.800000 ;
    END
  END head_record[188]
  PIN head_record[189]
    DIRECTION INPUT ;
    USE SIGNAL ;
    PORT
      LAYER M5 ;
      RECT 22.944000 64.716000 22.968000 64.800000 ;
    END
  END head_record[189]
  PIN head_record[190]
    DIRECTION INPUT ;
    USE SIGNAL ;
    PORT
      LAYER M5 ;
      RECT 23.328000 64.716000 23.352000 64.800000 ;
    END
  END head_record[190]
  PIN head_record[191]
    DIRECTION INPUT ;
    USE SIGNAL ;
    PORT
      LAYER M5 ;
      RECT 23.712000 64.716000 23.736000 64.800000 ;
    END
  END head_record[191]
  PIN head_record[192]
    DIRECTION INPUT ;
    USE SIGNAL ;
    PORT
      LAYER M5 ;
      RECT 24.144000 64.716000 24.168000 64.800000 ;
    END
  END head_record[192]
  PIN head_record[193]
    DIRECTION INPUT ;
    USE SIGNAL ;
    PORT
      LAYER M5 ;
      RECT 24.528000 64.716000 24.552000 64.800000 ;
    END
  END head_record[193]
  PIN head_record[194]
    DIRECTION INPUT ;
    USE SIGNAL ;
    PORT
      LAYER M5 ;
      RECT 24.960000 64.716000 24.984000 64.800000 ;
    END
  END head_record[194]
  PIN head_record[195]
    DIRECTION INPUT ;
    USE SIGNAL ;
    PORT
      LAYER M5 ;
      RECT 25.344000 64.716000 25.368000 64.800000 ;
    END
  END head_record[195]
  PIN head_record[196]
    DIRECTION INPUT ;
    USE SIGNAL ;
    PORT
      LAYER M5 ;
      RECT 25.728000 64.716000 25.752000 64.800000 ;
    END
  END head_record[196]
  PIN head_record[197]
    DIRECTION INPUT ;
    USE SIGNAL ;
    PORT
      LAYER M5 ;
      RECT 26.160000 64.716000 26.184000 64.800000 ;
    END
  END head_record[197]
  PIN head_record[198]
    DIRECTION INPUT ;
    USE SIGNAL ;
    PORT
      LAYER M5 ;
      RECT 26.544000 64.716000 26.568000 64.800000 ;
    END
  END head_record[198]
  PIN head_record[199]
    DIRECTION INPUT ;
    USE SIGNAL ;
    PORT
      LAYER M5 ;
      RECT 26.976000 64.716000 27.000000 64.800000 ;
    END
  END head_record[199]
  PIN head_record[200]
    DIRECTION INPUT ;
    USE SIGNAL ;
    PORT
      LAYER M5 ;
      RECT 27.360000 64.716000 27.384000 64.800000 ;
    END
  END head_record[200]
  PIN head_record[201]
    DIRECTION INPUT ;
    USE SIGNAL ;
    PORT
      LAYER M5 ;
      RECT 27.744000 64.716000 27.768000 64.800000 ;
    END
  END head_record[201]
  PIN head_record[202]
    DIRECTION INPUT ;
    USE SIGNAL ;
    PORT
      LAYER M5 ;
      RECT 28.176000 64.716000 28.200000 64.800000 ;
    END
  END head_record[202]
  PIN head_record[203]
    DIRECTION INPUT ;
    USE SIGNAL ;
    PORT
      LAYER M5 ;
      RECT 28.560000 64.716000 28.584000 64.800000 ;
    END
  END head_record[203]
  PIN head_record[204]
    DIRECTION INPUT ;
    USE SIGNAL ;
    PORT
      LAYER M5 ;
      RECT 28.944000 64.716000 28.968000 64.800000 ;
    END
  END head_record[204]
  PIN head_record[205]
    DIRECTION INPUT ;
    USE SIGNAL ;
    PORT
      LAYER M5 ;
      RECT 29.376000 64.716000 29.400000 64.800000 ;
    END
  END head_record[205]
  PIN head_record[206]
    DIRECTION INPUT ;
    USE SIGNAL ;
    PORT
      LAYER M5 ;
      RECT 29.760000 64.716000 29.784000 64.800000 ;
    END
  END head_record[206]
  PIN ck
    DIRECTION INPUT ;
    USE CLOCK ;
    PORT
      LAYER M5 ;
      RECT 30.192000 64.716000 30.216000 64.800000 ;
    END
  END ck
  PIN rst_n
    DIRECTION INPUT ;
    USE SIGNAL ;
    PORT
      LAYER M5 ;
      RECT 30.576000 64.716000 30.600000 64.800000 ;
    END
  END rst_n
  PIN ovl_users[0]
    DIRECTION INPUT ;
    USE SIGNAL ;
    PORT
      LAYER M5 ;
      RECT 30.960000 64.716000 30.984000 64.800000 ;
    END
  END ovl_users[0]
  PIN ovl_users[1]
    DIRECTION INPUT ;
    USE SIGNAL ;
    PORT
      LAYER M5 ;
      RECT 31.392000 64.716000 31.416000 64.800000 ;
    END
  END ovl_users[1]
  PIN ovl_users[2]
    DIRECTION INPUT ;
    USE SIGNAL ;
    PORT
      LAYER M5 ;
      RECT 31.776000 64.716000 31.800000 64.800000 ;
    END
  END ovl_users[2]
  PIN ovl_users[3]
    DIRECTION INPUT ;
    USE SIGNAL ;
    PORT
      LAYER M5 ;
      RECT 32.208000 64.716000 32.232000 64.800000 ;
    END
  END ovl_users[3]
  PIN calrx[0]
    DIRECTION INPUT ;
    USE SIGNAL ;
    PORT
      LAYER M5 ;
      RECT 32.592000 64.716000 32.616000 64.800000 ;
    END
  END calrx[0]
  PIN calrx[1]
    DIRECTION INPUT ;
    USE SIGNAL ;
    PORT
      LAYER M5 ;
      RECT 32.976000 64.716000 33.000000 64.800000 ;
    END
  END calrx[1]
  PIN calrx[2]
    DIRECTION INPUT ;
    USE SIGNAL ;
    PORT
      LAYER M5 ;
      RECT 33.408000 64.716000 33.432000 64.800000 ;
    END
  END calrx[2]
  PIN calrx[3]
    DIRECTION INPUT ;
    USE SIGNAL ;
    PORT
      LAYER M5 ;
      RECT 33.792000 64.716000 33.816000 64.800000 ;
    END
  END calrx[3]
  PIN adm_done
    DIRECTION INPUT ;
    USE SIGNAL ;
    PORT
      LAYER M5 ;
      RECT 34.176000 64.716000 34.200000 64.800000 ;
    END
  END adm_done
  PIN reseed
    DIRECTION INPUT ;
    USE SIGNAL ;
    PORT
      LAYER M5 ;
      RECT 34.608000 64.716000 34.632000 64.800000 ;
    END
  END reseed
  PIN head_record[207]
    DIRECTION INPUT ;
    USE SIGNAL ;
    PORT
      LAYER M5 ;
      RECT 34.992000 64.716000 35.016000 64.800000 ;
    END
  END head_record[207]
  PIN head_record[208]
    DIRECTION INPUT ;
    USE SIGNAL ;
    PORT
      LAYER M5 ;
      RECT 35.424000 64.716000 35.448000 64.800000 ;
    END
  END head_record[208]
  PIN head_record[209]
    DIRECTION INPUT ;
    USE SIGNAL ;
    PORT
      LAYER M5 ;
      RECT 35.808000 64.716000 35.832000 64.800000 ;
    END
  END head_record[209]
  PIN head_record[210]
    DIRECTION INPUT ;
    USE SIGNAL ;
    PORT
      LAYER M5 ;
      RECT 36.192000 64.716000 36.216000 64.800000 ;
    END
  END head_record[210]
  PIN head_record[211]
    DIRECTION INPUT ;
    USE SIGNAL ;
    PORT
      LAYER M5 ;
      RECT 36.624000 64.716000 36.648000 64.800000 ;
    END
  END head_record[211]
  PIN head_record[212]
    DIRECTION INPUT ;
    USE SIGNAL ;
    PORT
      LAYER M5 ;
      RECT 37.008000 64.716000 37.032000 64.800000 ;
    END
  END head_record[212]
  PIN head_record[213]
    DIRECTION INPUT ;
    USE SIGNAL ;
    PORT
      LAYER M5 ;
      RECT 37.440000 64.716000 37.464000 64.800000 ;
    END
  END head_record[213]
  PIN head_record[214]
    DIRECTION INPUT ;
    USE SIGNAL ;
    PORT
      LAYER M5 ;
      RECT 37.824000 64.716000 37.848000 64.800000 ;
    END
  END head_record[214]
  PIN head_record[215]
    DIRECTION INPUT ;
    USE SIGNAL ;
    PORT
      LAYER M5 ;
      RECT 38.208000 64.716000 38.232000 64.800000 ;
    END
  END head_record[215]
  PIN head_record[216]
    DIRECTION INPUT ;
    USE SIGNAL ;
    PORT
      LAYER M5 ;
      RECT 38.640000 64.716000 38.664000 64.800000 ;
    END
  END head_record[216]
  PIN head_record[217]
    DIRECTION INPUT ;
    USE SIGNAL ;
    PORT
      LAYER M5 ;
      RECT 39.024000 64.716000 39.048000 64.800000 ;
    END
  END head_record[217]
  PIN head_record[218]
    DIRECTION INPUT ;
    USE SIGNAL ;
    PORT
      LAYER M5 ;
      RECT 39.456000 64.716000 39.480000 64.800000 ;
    END
  END head_record[218]
  PIN head_record[219]
    DIRECTION INPUT ;
    USE SIGNAL ;
    PORT
      LAYER M5 ;
      RECT 39.840000 64.716000 39.864000 64.800000 ;
    END
  END head_record[219]
  PIN head_record[220]
    DIRECTION INPUT ;
    USE SIGNAL ;
    PORT
      LAYER M5 ;
      RECT 40.224000 64.716000 40.248000 64.800000 ;
    END
  END head_record[220]
  PIN head_record[221]
    DIRECTION INPUT ;
    USE SIGNAL ;
    PORT
      LAYER M5 ;
      RECT 40.656000 64.716000 40.680000 64.800000 ;
    END
  END head_record[221]
  PIN head_record[222]
    DIRECTION INPUT ;
    USE SIGNAL ;
    PORT
      LAYER M5 ;
      RECT 41.040000 64.716000 41.064000 64.800000 ;
    END
  END head_record[222]
  PIN head_record[223]
    DIRECTION INPUT ;
    USE SIGNAL ;
    PORT
      LAYER M5 ;
      RECT 41.424000 64.716000 41.448000 64.800000 ;
    END
  END head_record[223]
  PIN head_record[224]
    DIRECTION INPUT ;
    USE SIGNAL ;
    PORT
      LAYER M5 ;
      RECT 41.856000 64.716000 41.880000 64.800000 ;
    END
  END head_record[224]
  PIN head_record[225]
    DIRECTION INPUT ;
    USE SIGNAL ;
    PORT
      LAYER M5 ;
      RECT 42.240000 64.716000 42.264000 64.800000 ;
    END
  END head_record[225]
  PIN head_record[226]
    DIRECTION INPUT ;
    USE SIGNAL ;
    PORT
      LAYER M5 ;
      RECT 42.672000 64.716000 42.696000 64.800000 ;
    END
  END head_record[226]
  PIN head_record[227]
    DIRECTION INPUT ;
    USE SIGNAL ;
    PORT
      LAYER M5 ;
      RECT 43.056000 64.716000 43.080000 64.800000 ;
    END
  END head_record[227]
  PIN head_record[228]
    DIRECTION INPUT ;
    USE SIGNAL ;
    PORT
      LAYER M5 ;
      RECT 43.440000 64.716000 43.464000 64.800000 ;
    END
  END head_record[228]
  PIN head_record[229]
    DIRECTION INPUT ;
    USE SIGNAL ;
    PORT
      LAYER M5 ;
      RECT 43.872000 64.716000 43.896000 64.800000 ;
    END
  END head_record[229]
  PIN head_record[230]
    DIRECTION INPUT ;
    USE SIGNAL ;
    PORT
      LAYER M5 ;
      RECT 44.256000 64.716000 44.280000 64.800000 ;
    END
  END head_record[230]
  PIN head_record[231]
    DIRECTION INPUT ;
    USE SIGNAL ;
    PORT
      LAYER M5 ;
      RECT 44.688000 64.716000 44.712000 64.800000 ;
    END
  END head_record[231]
  PIN head_record[232]
    DIRECTION INPUT ;
    USE SIGNAL ;
    PORT
      LAYER M5 ;
      RECT 45.072000 64.716000 45.096000 64.800000 ;
    END
  END head_record[232]
  PIN head_record[233]
    DIRECTION INPUT ;
    USE SIGNAL ;
    PORT
      LAYER M5 ;
      RECT 45.456000 64.716000 45.480000 64.800000 ;
    END
  END head_record[233]
  PIN head_record[234]
    DIRECTION INPUT ;
    USE SIGNAL ;
    PORT
      LAYER M5 ;
      RECT 45.888000 64.716000 45.912000 64.800000 ;
    END
  END head_record[234]
  PIN head_record[235]
    DIRECTION INPUT ;
    USE SIGNAL ;
    PORT
      LAYER M5 ;
      RECT 46.272000 64.716000 46.296000 64.800000 ;
    END
  END head_record[235]
  PIN head_record[236]
    DIRECTION INPUT ;
    USE SIGNAL ;
    PORT
      LAYER M5 ;
      RECT 46.656000 64.716000 46.680000 64.800000 ;
    END
  END head_record[236]
  PIN head_record[237]
    DIRECTION INPUT ;
    USE SIGNAL ;
    PORT
      LAYER M5 ;
      RECT 47.088000 64.716000 47.112000 64.800000 ;
    END
  END head_record[237]
  PIN head_record[238]
    DIRECTION INPUT ;
    USE SIGNAL ;
    PORT
      LAYER M5 ;
      RECT 47.472000 64.716000 47.496000 64.800000 ;
    END
  END head_record[238]
  PIN head_record[239]
    DIRECTION INPUT ;
    USE SIGNAL ;
    PORT
      LAYER M5 ;
      RECT 47.904000 64.716000 47.928000 64.800000 ;
    END
  END head_record[239]
  PIN head_record[240]
    DIRECTION INPUT ;
    USE SIGNAL ;
    PORT
      LAYER M5 ;
      RECT 48.288000 64.716000 48.312000 64.800000 ;
    END
  END head_record[240]
  PIN head_record[241]
    DIRECTION INPUT ;
    USE SIGNAL ;
    PORT
      LAYER M5 ;
      RECT 48.672000 64.716000 48.696000 64.800000 ;
    END
  END head_record[241]
  PIN head_record[242]
    DIRECTION INPUT ;
    USE SIGNAL ;
    PORT
      LAYER M5 ;
      RECT 49.104000 64.716000 49.128000 64.800000 ;
    END
  END head_record[242]
  PIN head_record[243]
    DIRECTION INPUT ;
    USE SIGNAL ;
    PORT
      LAYER M5 ;
      RECT 49.488000 64.716000 49.512000 64.800000 ;
    END
  END head_record[243]
  PIN head_record[244]
    DIRECTION INPUT ;
    USE SIGNAL ;
    PORT
      LAYER M5 ;
      RECT 49.920000 64.716000 49.944000 64.800000 ;
    END
  END head_record[244]
  PIN head_record[245]
    DIRECTION INPUT ;
    USE SIGNAL ;
    PORT
      LAYER M5 ;
      RECT 50.304000 64.716000 50.328000 64.800000 ;
    END
  END head_record[245]
  PIN head_record[246]
    DIRECTION INPUT ;
    USE SIGNAL ;
    PORT
      LAYER M5 ;
      RECT 50.688000 64.716000 50.712000 64.800000 ;
    END
  END head_record[246]
  PIN head_record[247]
    DIRECTION INPUT ;
    USE SIGNAL ;
    PORT
      LAYER M5 ;
      RECT 51.120000 64.716000 51.144000 64.800000 ;
    END
  END head_record[247]
  PIN head_record[248]
    DIRECTION INPUT ;
    USE SIGNAL ;
    PORT
      LAYER M5 ;
      RECT 51.504000 64.716000 51.528000 64.800000 ;
    END
  END head_record[248]
  PIN head_record[249]
    DIRECTION INPUT ;
    USE SIGNAL ;
    PORT
      LAYER M5 ;
      RECT 51.936000 64.716000 51.960000 64.800000 ;
    END
  END head_record[249]
  PIN head_record[250]
    DIRECTION INPUT ;
    USE SIGNAL ;
    PORT
      LAYER M5 ;
      RECT 52.320000 64.716000 52.344000 64.800000 ;
    END
  END head_record[250]
  PIN head_record[251]
    DIRECTION INPUT ;
    USE SIGNAL ;
    PORT
      LAYER M5 ;
      RECT 52.704000 64.716000 52.728000 64.800000 ;
    END
  END head_record[251]
  PIN head_record[252]
    DIRECTION INPUT ;
    USE SIGNAL ;
    PORT
      LAYER M5 ;
      RECT 53.136000 64.716000 53.160000 64.800000 ;
    END
  END head_record[252]
  PIN head_record[253]
    DIRECTION INPUT ;
    USE SIGNAL ;
    PORT
      LAYER M5 ;
      RECT 53.520000 64.716000 53.544000 64.800000 ;
    END
  END head_record[253]
  PIN head_record[254]
    DIRECTION INPUT ;
    USE SIGNAL ;
    PORT
      LAYER M5 ;
      RECT 53.904000 64.716000 53.928000 64.800000 ;
    END
  END head_record[254]
  PIN head_record[255]
    DIRECTION INPUT ;
    USE SIGNAL ;
    PORT
      LAYER M5 ;
      RECT 54.336000 64.716000 54.360000 64.800000 ;
    END
  END head_record[255]
  PIN head_record[256]
    DIRECTION INPUT ;
    USE SIGNAL ;
    PORT
      LAYER M5 ;
      RECT 54.720000 64.716000 54.744000 64.800000 ;
    END
  END head_record[256]
  PIN head_record[257]
    DIRECTION INPUT ;
    USE SIGNAL ;
    PORT
      LAYER M5 ;
      RECT 55.152000 64.716000 55.176000 64.800000 ;
    END
  END head_record[257]
  PIN head_record[258]
    DIRECTION INPUT ;
    USE SIGNAL ;
    PORT
      LAYER M5 ;
      RECT 55.536000 64.716000 55.560000 64.800000 ;
    END
  END head_record[258]
  PIN head_record[259]
    DIRECTION INPUT ;
    USE SIGNAL ;
    PORT
      LAYER M5 ;
      RECT 55.920000 64.716000 55.944000 64.800000 ;
    END
  END head_record[259]
  PIN head_record[260]
    DIRECTION INPUT ;
    USE SIGNAL ;
    PORT
      LAYER M5 ;
      RECT 56.352000 64.716000 56.376000 64.800000 ;
    END
  END head_record[260]
  PIN head_record[261]
    DIRECTION INPUT ;
    USE SIGNAL ;
    PORT
      LAYER M5 ;
      RECT 56.736000 64.716000 56.760000 64.800000 ;
    END
  END head_record[261]
  PIN head_record[262]
    DIRECTION INPUT ;
    USE SIGNAL ;
    PORT
      LAYER M5 ;
      RECT 57.168000 64.716000 57.192000 64.800000 ;
    END
  END head_record[262]
  PIN head_record[263]
    DIRECTION INPUT ;
    USE SIGNAL ;
    PORT
      LAYER M5 ;
      RECT 57.552000 64.716000 57.576000 64.800000 ;
    END
  END head_record[263]
  PIN head_record[264]
    DIRECTION INPUT ;
    USE SIGNAL ;
    PORT
      LAYER M5 ;
      RECT 57.936000 64.716000 57.960000 64.800000 ;
    END
  END head_record[264]
  PIN head_record[265]
    DIRECTION INPUT ;
    USE SIGNAL ;
    PORT
      LAYER M5 ;
      RECT 58.368000 64.716000 58.392000 64.800000 ;
    END
  END head_record[265]
  PIN head_record[266]
    DIRECTION INPUT ;
    USE SIGNAL ;
    PORT
      LAYER M5 ;
      RECT 58.752000 64.716000 58.776000 64.800000 ;
    END
  END head_record[266]
  PIN head_record[267]
    DIRECTION INPUT ;
    USE SIGNAL ;
    PORT
      LAYER M5 ;
      RECT 59.136000 64.716000 59.160000 64.800000 ;
    END
  END head_record[267]
  PIN head_record[268]
    DIRECTION INPUT ;
    USE SIGNAL ;
    PORT
      LAYER M5 ;
      RECT 59.568000 64.716000 59.592000 64.800000 ;
    END
  END head_record[268]
  PIN head_record[269]
    DIRECTION INPUT ;
    USE SIGNAL ;
    PORT
      LAYER M5 ;
      RECT 59.952000 64.716000 59.976000 64.800000 ;
    END
  END head_record[269]
  PIN head_record[270]
    DIRECTION INPUT ;
    USE SIGNAL ;
    PORT
      LAYER M5 ;
      RECT 60.384000 64.716000 60.408000 64.800000 ;
    END
  END head_record[270]
  PIN head_record[271]
    DIRECTION INPUT ;
    USE SIGNAL ;
    PORT
      LAYER M5 ;
      RECT 60.768000 64.716000 60.792000 64.800000 ;
    END
  END head_record[271]
  PIN head_record[272]
    DIRECTION INPUT ;
    USE SIGNAL ;
    PORT
      LAYER M5 ;
      RECT 61.152000 64.716000 61.176000 64.800000 ;
    END
  END head_record[272]
  PIN head_record[273]
    DIRECTION INPUT ;
    USE SIGNAL ;
    PORT
      LAYER M5 ;
      RECT 61.584000 64.716000 61.608000 64.800000 ;
    END
  END head_record[273]
  PIN head_record[274]
    DIRECTION INPUT ;
    USE SIGNAL ;
    PORT
      LAYER M5 ;
      RECT 61.968000 64.716000 61.992000 64.800000 ;
    END
  END head_record[274]
  PIN head_record[275]
    DIRECTION INPUT ;
    USE SIGNAL ;
    PORT
      LAYER M5 ;
      RECT 62.400000 64.716000 62.424000 64.800000 ;
    END
  END head_record[275]
  PIN head_record[276]
    DIRECTION INPUT ;
    USE SIGNAL ;
    PORT
      LAYER M5 ;
      RECT 2.400000 0.000000 2.424000 0.084000 ;
    END
  END head_record[276]
  PIN head_record[277]
    DIRECTION INPUT ;
    USE SIGNAL ;
    PORT
      LAYER M5 ;
      RECT 2.832000 0.000000 2.856000 0.084000 ;
    END
  END head_record[277]
  PIN head_record[278]
    DIRECTION INPUT ;
    USE SIGNAL ;
    PORT
      LAYER M5 ;
      RECT 3.312000 0.000000 3.336000 0.084000 ;
    END
  END head_record[278]
  PIN head_record[279]
    DIRECTION INPUT ;
    USE SIGNAL ;
    PORT
      LAYER M5 ;
      RECT 3.744000 0.000000 3.768000 0.084000 ;
    END
  END head_record[279]
  PIN head_record[280]
    DIRECTION INPUT ;
    USE SIGNAL ;
    PORT
      LAYER M5 ;
      RECT 4.176000 0.000000 4.200000 0.084000 ;
    END
  END head_record[280]
  PIN head_record[281]
    DIRECTION INPUT ;
    USE SIGNAL ;
    PORT
      LAYER M5 ;
      RECT 4.608000 0.000000 4.632000 0.084000 ;
    END
  END head_record[281]
  PIN head_record[282]
    DIRECTION INPUT ;
    USE SIGNAL ;
    PORT
      LAYER M5 ;
      RECT 5.040000 0.000000 5.064000 0.084000 ;
    END
  END head_record[282]
  PIN head_record[283]
    DIRECTION INPUT ;
    USE SIGNAL ;
    PORT
      LAYER M5 ;
      RECT 5.472000 0.000000 5.496000 0.084000 ;
    END
  END head_record[283]
  PIN head_record[284]
    DIRECTION INPUT ;
    USE SIGNAL ;
    PORT
      LAYER M5 ;
      RECT 5.904000 0.000000 5.928000 0.084000 ;
    END
  END head_record[284]
  PIN head_record[285]
    DIRECTION INPUT ;
    USE SIGNAL ;
    PORT
      LAYER M5 ;
      RECT 6.336000 0.000000 6.360000 0.084000 ;
    END
  END head_record[285]
  PIN head_record[286]
    DIRECTION INPUT ;
    USE SIGNAL ;
    PORT
      LAYER M5 ;
      RECT 6.768000 0.000000 6.792000 0.084000 ;
    END
  END head_record[286]
  PIN head_record[287]
    DIRECTION INPUT ;
    USE SIGNAL ;
    PORT
      LAYER M5 ;
      RECT 7.248000 0.000000 7.272000 0.084000 ;
    END
  END head_record[287]
  PIN head_record[288]
    DIRECTION INPUT ;
    USE SIGNAL ;
    PORT
      LAYER M5 ;
      RECT 7.680000 0.000000 7.704000 0.084000 ;
    END
  END head_record[288]
  PIN head_record[289]
    DIRECTION INPUT ;
    USE SIGNAL ;
    PORT
      LAYER M5 ;
      RECT 8.112000 0.000000 8.136000 0.084000 ;
    END
  END head_record[289]
  PIN head_record[290]
    DIRECTION INPUT ;
    USE SIGNAL ;
    PORT
      LAYER M5 ;
      RECT 8.544000 0.000000 8.568000 0.084000 ;
    END
  END head_record[290]
  PIN head_record[291]
    DIRECTION INPUT ;
    USE SIGNAL ;
    PORT
      LAYER M5 ;
      RECT 8.976000 0.000000 9.000000 0.084000 ;
    END
  END head_record[291]
  PIN head_record[292]
    DIRECTION INPUT ;
    USE SIGNAL ;
    PORT
      LAYER M5 ;
      RECT 9.408000 0.000000 9.432000 0.084000 ;
    END
  END head_record[292]
  PIN head_record[293]
    DIRECTION INPUT ;
    USE SIGNAL ;
    PORT
      LAYER M5 ;
      RECT 9.840000 0.000000 9.864000 0.084000 ;
    END
  END head_record[293]
  PIN head_record[294]
    DIRECTION INPUT ;
    USE SIGNAL ;
    PORT
      LAYER M5 ;
      RECT 10.272000 0.000000 10.296000 0.084000 ;
    END
  END head_record[294]
  PIN head_record[295]
    DIRECTION INPUT ;
    USE SIGNAL ;
    PORT
      LAYER M5 ;
      RECT 10.752000 0.000000 10.776000 0.084000 ;
    END
  END head_record[295]
  PIN head_record[296]
    DIRECTION INPUT ;
    USE SIGNAL ;
    PORT
      LAYER M5 ;
      RECT 11.184000 0.000000 11.208000 0.084000 ;
    END
  END head_record[296]
  PIN head_record[297]
    DIRECTION INPUT ;
    USE SIGNAL ;
    PORT
      LAYER M5 ;
      RECT 11.616000 0.000000 11.640000 0.084000 ;
    END
  END head_record[297]
  PIN head_record[298]
    DIRECTION INPUT ;
    USE SIGNAL ;
    PORT
      LAYER M5 ;
      RECT 12.048000 0.000000 12.072000 0.084000 ;
    END
  END head_record[298]
  PIN head_record[299]
    DIRECTION INPUT ;
    USE SIGNAL ;
    PORT
      LAYER M5 ;
      RECT 12.480000 0.000000 12.504000 0.084000 ;
    END
  END head_record[299]
  PIN head_record[300]
    DIRECTION INPUT ;
    USE SIGNAL ;
    PORT
      LAYER M5 ;
      RECT 12.912000 0.000000 12.936000 0.084000 ;
    END
  END head_record[300]
  PIN head_record[301]
    DIRECTION INPUT ;
    USE SIGNAL ;
    PORT
      LAYER M5 ;
      RECT 13.344000 0.000000 13.368000 0.084000 ;
    END
  END head_record[301]
  PIN head_record[302]
    DIRECTION INPUT ;
    USE SIGNAL ;
    PORT
      LAYER M5 ;
      RECT 13.776000 0.000000 13.800000 0.084000 ;
    END
  END head_record[302]
  PIN head_record[303]
    DIRECTION INPUT ;
    USE SIGNAL ;
    PORT
      LAYER M5 ;
      RECT 14.208000 0.000000 14.232000 0.084000 ;
    END
  END head_record[303]
  PIN head_record[304]
    DIRECTION INPUT ;
    USE SIGNAL ;
    PORT
      LAYER M5 ;
      RECT 14.688000 0.000000 14.712000 0.084000 ;
    END
  END head_record[304]
  PIN head_record[305]
    DIRECTION INPUT ;
    USE SIGNAL ;
    PORT
      LAYER M5 ;
      RECT 15.120000 0.000000 15.144000 0.084000 ;
    END
  END head_record[305]
  PIN head_record[306]
    DIRECTION INPUT ;
    USE SIGNAL ;
    PORT
      LAYER M5 ;
      RECT 15.552000 0.000000 15.576000 0.084000 ;
    END
  END head_record[306]
  PIN head_record[307]
    DIRECTION INPUT ;
    USE SIGNAL ;
    PORT
      LAYER M5 ;
      RECT 15.984000 0.000000 16.008000 0.084000 ;
    END
  END head_record[307]
  PIN head_record[308]
    DIRECTION INPUT ;
    USE SIGNAL ;
    PORT
      LAYER M5 ;
      RECT 16.416000 0.000000 16.440000 0.084000 ;
    END
  END head_record[308]
  PIN head_record[309]
    DIRECTION INPUT ;
    USE SIGNAL ;
    PORT
      LAYER M5 ;
      RECT 16.848000 0.000000 16.872000 0.084000 ;
    END
  END head_record[309]
  PIN head_record[310]
    DIRECTION INPUT ;
    USE SIGNAL ;
    PORT
      LAYER M5 ;
      RECT 17.280000 0.000000 17.304000 0.084000 ;
    END
  END head_record[310]
  PIN head_record[311]
    DIRECTION INPUT ;
    USE SIGNAL ;
    PORT
      LAYER M5 ;
      RECT 17.712000 0.000000 17.736000 0.084000 ;
    END
  END head_record[311]
  PIN head_record[312]
    DIRECTION INPUT ;
    USE SIGNAL ;
    PORT
      LAYER M5 ;
      RECT 18.144000 0.000000 18.168000 0.084000 ;
    END
  END head_record[312]
  PIN head_record[313]
    DIRECTION INPUT ;
    USE SIGNAL ;
    PORT
      LAYER M5 ;
      RECT 18.624000 0.000000 18.648000 0.084000 ;
    END
  END head_record[313]
  PIN head_record[314]
    DIRECTION INPUT ;
    USE SIGNAL ;
    PORT
      LAYER M5 ;
      RECT 19.056000 0.000000 19.080000 0.084000 ;
    END
  END head_record[314]
  PIN head_record[315]
    DIRECTION INPUT ;
    USE SIGNAL ;
    PORT
      LAYER M5 ;
      RECT 19.488000 0.000000 19.512000 0.084000 ;
    END
  END head_record[315]
  PIN head_record[316]
    DIRECTION INPUT ;
    USE SIGNAL ;
    PORT
      LAYER M5 ;
      RECT 19.920000 0.000000 19.944000 0.084000 ;
    END
  END head_record[316]
  PIN head_record[317]
    DIRECTION INPUT ;
    USE SIGNAL ;
    PORT
      LAYER M5 ;
      RECT 20.352000 0.000000 20.376000 0.084000 ;
    END
  END head_record[317]
  PIN head_record[318]
    DIRECTION INPUT ;
    USE SIGNAL ;
    PORT
      LAYER M5 ;
      RECT 20.784000 0.000000 20.808000 0.084000 ;
    END
  END head_record[318]
  PIN head_record[319]
    DIRECTION INPUT ;
    USE SIGNAL ;
    PORT
      LAYER M5 ;
      RECT 21.216000 0.000000 21.240000 0.084000 ;
    END
  END head_record[319]
  PIN head_record[320]
    DIRECTION INPUT ;
    USE SIGNAL ;
    PORT
      LAYER M5 ;
      RECT 21.648000 0.000000 21.672000 0.084000 ;
    END
  END head_record[320]
  PIN head_record[321]
    DIRECTION INPUT ;
    USE SIGNAL ;
    PORT
      LAYER M5 ;
      RECT 22.128000 0.000000 22.152000 0.084000 ;
    END
  END head_record[321]
  PIN head_record[322]
    DIRECTION INPUT ;
    USE SIGNAL ;
    PORT
      LAYER M5 ;
      RECT 22.560000 0.000000 22.584000 0.084000 ;
    END
  END head_record[322]
  PIN head_record[323]
    DIRECTION INPUT ;
    USE SIGNAL ;
    PORT
      LAYER M5 ;
      RECT 22.992000 0.000000 23.016000 0.084000 ;
    END
  END head_record[323]
  PIN head_record[324]
    DIRECTION INPUT ;
    USE SIGNAL ;
    PORT
      LAYER M5 ;
      RECT 23.424000 0.000000 23.448000 0.084000 ;
    END
  END head_record[324]
  PIN head_record[325]
    DIRECTION INPUT ;
    USE SIGNAL ;
    PORT
      LAYER M5 ;
      RECT 23.856000 0.000000 23.880000 0.084000 ;
    END
  END head_record[325]
  PIN head_record[326]
    DIRECTION INPUT ;
    USE SIGNAL ;
    PORT
      LAYER M5 ;
      RECT 24.288000 0.000000 24.312000 0.084000 ;
    END
  END head_record[326]
  PIN head_record[327]
    DIRECTION INPUT ;
    USE SIGNAL ;
    PORT
      LAYER M5 ;
      RECT 24.720000 0.000000 24.744000 0.084000 ;
    END
  END head_record[327]
  PIN head_record[328]
    DIRECTION INPUT ;
    USE SIGNAL ;
    PORT
      LAYER M5 ;
      RECT 25.152000 0.000000 25.176000 0.084000 ;
    END
  END head_record[328]
  PIN head_record[329]
    DIRECTION INPUT ;
    USE SIGNAL ;
    PORT
      LAYER M5 ;
      RECT 25.584000 0.000000 25.608000 0.084000 ;
    END
  END head_record[329]
  PIN head_record[330]
    DIRECTION INPUT ;
    USE SIGNAL ;
    PORT
      LAYER M5 ;
      RECT 26.064000 0.000000 26.088000 0.084000 ;
    END
  END head_record[330]
  PIN head_record[331]
    DIRECTION INPUT ;
    USE SIGNAL ;
    PORT
      LAYER M5 ;
      RECT 26.496000 0.000000 26.520000 0.084000 ;
    END
  END head_record[331]
  PIN head_record[332]
    DIRECTION INPUT ;
    USE SIGNAL ;
    PORT
      LAYER M5 ;
      RECT 26.928000 0.000000 26.952000 0.084000 ;
    END
  END head_record[332]
  PIN head_record[333]
    DIRECTION INPUT ;
    USE SIGNAL ;
    PORT
      LAYER M5 ;
      RECT 27.360000 0.000000 27.384000 0.084000 ;
    END
  END head_record[333]
  PIN head_record[334]
    DIRECTION INPUT ;
    USE SIGNAL ;
    PORT
      LAYER M5 ;
      RECT 27.792000 0.000000 27.816000 0.084000 ;
    END
  END head_record[334]
  PIN head_record[335]
    DIRECTION INPUT ;
    USE SIGNAL ;
    PORT
      LAYER M5 ;
      RECT 28.224000 0.000000 28.248000 0.084000 ;
    END
  END head_record[335]
  PIN head_record[336]
    DIRECTION INPUT ;
    USE SIGNAL ;
    PORT
      LAYER M5 ;
      RECT 28.656000 0.000000 28.680000 0.084000 ;
    END
  END head_record[336]
  PIN head_record[337]
    DIRECTION INPUT ;
    USE SIGNAL ;
    PORT
      LAYER M5 ;
      RECT 29.088000 0.000000 29.112000 0.084000 ;
    END
  END head_record[337]
  PIN head_record[338]
    DIRECTION INPUT ;
    USE SIGNAL ;
    PORT
      LAYER M5 ;
      RECT 29.520000 0.000000 29.544000 0.084000 ;
    END
  END head_record[338]
  PIN head_record[339]
    DIRECTION INPUT ;
    USE SIGNAL ;
    PORT
      LAYER M5 ;
      RECT 30.000000 0.000000 30.024000 0.084000 ;
    END
  END head_record[339]
  PIN head_record[340]
    DIRECTION INPUT ;
    USE SIGNAL ;
    PORT
      LAYER M5 ;
      RECT 30.432000 0.000000 30.456000 0.084000 ;
    END
  END head_record[340]
  PIN head_record[341]
    DIRECTION INPUT ;
    USE SIGNAL ;
    PORT
      LAYER M5 ;
      RECT 30.864000 0.000000 30.888000 0.084000 ;
    END
  END head_record[341]
  PIN head_record[342]
    DIRECTION INPUT ;
    USE SIGNAL ;
    PORT
      LAYER M5 ;
      RECT 31.296000 0.000000 31.320000 0.084000 ;
    END
  END head_record[342]
  PIN head_record[343]
    DIRECTION INPUT ;
    USE SIGNAL ;
    PORT
      LAYER M5 ;
      RECT 31.728000 0.000000 31.752000 0.084000 ;
    END
  END head_record[343]
  PIN head_record[344]
    DIRECTION INPUT ;
    USE SIGNAL ;
    PORT
      LAYER M5 ;
      RECT 32.160000 0.000000 32.184000 0.084000 ;
    END
  END head_record[344]
  PIN head_record[345]
    DIRECTION INPUT ;
    USE SIGNAL ;
    PORT
      LAYER M5 ;
      RECT 32.592000 0.000000 32.616000 0.084000 ;
    END
  END head_record[345]
  PIN head_record[346]
    DIRECTION INPUT ;
    USE SIGNAL ;
    PORT
      LAYER M5 ;
      RECT 33.024000 0.000000 33.048000 0.084000 ;
    END
  END head_record[346]
  PIN head_record[347]
    DIRECTION INPUT ;
    USE SIGNAL ;
    PORT
      LAYER M5 ;
      RECT 33.504000 0.000000 33.528000 0.084000 ;
    END
  END head_record[347]
  PIN head_record[348]
    DIRECTION INPUT ;
    USE SIGNAL ;
    PORT
      LAYER M5 ;
      RECT 33.936000 0.000000 33.960000 0.084000 ;
    END
  END head_record[348]
  PIN head_record[349]
    DIRECTION INPUT ;
    USE SIGNAL ;
    PORT
      LAYER M5 ;
      RECT 34.368000 0.000000 34.392000 0.084000 ;
    END
  END head_record[349]
  PIN head_record[350]
    DIRECTION INPUT ;
    USE SIGNAL ;
    PORT
      LAYER M5 ;
      RECT 34.800000 0.000000 34.824000 0.084000 ;
    END
  END head_record[350]
  PIN head_record[351]
    DIRECTION INPUT ;
    USE SIGNAL ;
    PORT
      LAYER M5 ;
      RECT 35.232000 0.000000 35.256000 0.084000 ;
    END
  END head_record[351]
  PIN head_record[352]
    DIRECTION INPUT ;
    USE SIGNAL ;
    PORT
      LAYER M5 ;
      RECT 35.664000 0.000000 35.688000 0.084000 ;
    END
  END head_record[352]
  PIN head_record[353]
    DIRECTION INPUT ;
    USE SIGNAL ;
    PORT
      LAYER M5 ;
      RECT 36.096000 0.000000 36.120000 0.084000 ;
    END
  END head_record[353]
  PIN head_record[354]
    DIRECTION INPUT ;
    USE SIGNAL ;
    PORT
      LAYER M5 ;
      RECT 36.528000 0.000000 36.552000 0.084000 ;
    END
  END head_record[354]
  PIN head_record[355]
    DIRECTION INPUT ;
    USE SIGNAL ;
    PORT
      LAYER M5 ;
      RECT 36.960000 0.000000 36.984000 0.084000 ;
    END
  END head_record[355]
  PIN head_record[356]
    DIRECTION INPUT ;
    USE SIGNAL ;
    PORT
      LAYER M5 ;
      RECT 37.440000 0.000000 37.464000 0.084000 ;
    END
  END head_record[356]
  PIN head_record[357]
    DIRECTION INPUT ;
    USE SIGNAL ;
    PORT
      LAYER M5 ;
      RECT 37.872000 0.000000 37.896000 0.084000 ;
    END
  END head_record[357]
  PIN head_record[358]
    DIRECTION INPUT ;
    USE SIGNAL ;
    PORT
      LAYER M5 ;
      RECT 38.304000 0.000000 38.328000 0.084000 ;
    END
  END head_record[358]
  PIN head_record[359]
    DIRECTION INPUT ;
    USE SIGNAL ;
    PORT
      LAYER M5 ;
      RECT 38.736000 0.000000 38.760000 0.084000 ;
    END
  END head_record[359]
  PIN head_record[360]
    DIRECTION INPUT ;
    USE SIGNAL ;
    PORT
      LAYER M5 ;
      RECT 39.168000 0.000000 39.192000 0.084000 ;
    END
  END head_record[360]
  PIN head_record[361]
    DIRECTION INPUT ;
    USE SIGNAL ;
    PORT
      LAYER M5 ;
      RECT 39.600000 0.000000 39.624000 0.084000 ;
    END
  END head_record[361]
  PIN head_record[362]
    DIRECTION INPUT ;
    USE SIGNAL ;
    PORT
      LAYER M5 ;
      RECT 40.032000 0.000000 40.056000 0.084000 ;
    END
  END head_record[362]
  PIN head_record[363]
    DIRECTION INPUT ;
    USE SIGNAL ;
    PORT
      LAYER M5 ;
      RECT 40.464000 0.000000 40.488000 0.084000 ;
    END
  END head_record[363]
  PIN head_record[364]
    DIRECTION INPUT ;
    USE SIGNAL ;
    PORT
      LAYER M5 ;
      RECT 40.944000 0.000000 40.968000 0.084000 ;
    END
  END head_record[364]
  PIN head_record[365]
    DIRECTION INPUT ;
    USE SIGNAL ;
    PORT
      LAYER M5 ;
      RECT 41.376000 0.000000 41.400000 0.084000 ;
    END
  END head_record[365]
  PIN head_record[366]
    DIRECTION INPUT ;
    USE SIGNAL ;
    PORT
      LAYER M5 ;
      RECT 41.808000 0.000000 41.832000 0.084000 ;
    END
  END head_record[366]
  PIN head_record[367]
    DIRECTION INPUT ;
    USE SIGNAL ;
    PORT
      LAYER M5 ;
      RECT 42.240000 0.000000 42.264000 0.084000 ;
    END
  END head_record[367]
  PIN head_record[368]
    DIRECTION INPUT ;
    USE SIGNAL ;
    PORT
      LAYER M5 ;
      RECT 42.672000 0.000000 42.696000 0.084000 ;
    END
  END head_record[368]
  PIN head_record[369]
    DIRECTION INPUT ;
    USE SIGNAL ;
    PORT
      LAYER M5 ;
      RECT 43.104000 0.000000 43.128000 0.084000 ;
    END
  END head_record[369]
  PIN head_record[370]
    DIRECTION INPUT ;
    USE SIGNAL ;
    PORT
      LAYER M5 ;
      RECT 43.536000 0.000000 43.560000 0.084000 ;
    END
  END head_record[370]
  PIN head_record[371]
    DIRECTION INPUT ;
    USE SIGNAL ;
    PORT
      LAYER M5 ;
      RECT 43.968000 0.000000 43.992000 0.084000 ;
    END
  END head_record[371]
  PIN head_record[372]
    DIRECTION INPUT ;
    USE SIGNAL ;
    PORT
      LAYER M5 ;
      RECT 44.400000 0.000000 44.424000 0.084000 ;
    END
  END head_record[372]
  PIN head_record[373]
    DIRECTION INPUT ;
    USE SIGNAL ;
    PORT
      LAYER M5 ;
      RECT 44.880000 0.000000 44.904000 0.084000 ;
    END
  END head_record[373]
  PIN head_record[374]
    DIRECTION INPUT ;
    USE SIGNAL ;
    PORT
      LAYER M5 ;
      RECT 45.312000 0.000000 45.336000 0.084000 ;
    END
  END head_record[374]
  PIN head_record[375]
    DIRECTION INPUT ;
    USE SIGNAL ;
    PORT
      LAYER M5 ;
      RECT 45.744000 0.000000 45.768000 0.084000 ;
    END
  END head_record[375]
  PIN head_record[376]
    DIRECTION INPUT ;
    USE SIGNAL ;
    PORT
      LAYER M5 ;
      RECT 46.176000 0.000000 46.200000 0.084000 ;
    END
  END head_record[376]
  PIN head_record[377]
    DIRECTION INPUT ;
    USE SIGNAL ;
    PORT
      LAYER M5 ;
      RECT 46.608000 0.000000 46.632000 0.084000 ;
    END
  END head_record[377]
  PIN head_record[378]
    DIRECTION INPUT ;
    USE SIGNAL ;
    PORT
      LAYER M5 ;
      RECT 47.040000 0.000000 47.064000 0.084000 ;
    END
  END head_record[378]
  PIN head_record[379]
    DIRECTION INPUT ;
    USE SIGNAL ;
    PORT
      LAYER M5 ;
      RECT 47.472000 0.000000 47.496000 0.084000 ;
    END
  END head_record[379]
  PIN head_record[380]
    DIRECTION INPUT ;
    USE SIGNAL ;
    PORT
      LAYER M5 ;
      RECT 47.904000 0.000000 47.928000 0.084000 ;
    END
  END head_record[380]
  PIN head_record[381]
    DIRECTION INPUT ;
    USE SIGNAL ;
    PORT
      LAYER M5 ;
      RECT 48.336000 0.000000 48.360000 0.084000 ;
    END
  END head_record[381]
  PIN head_record[382]
    DIRECTION INPUT ;
    USE SIGNAL ;
    PORT
      LAYER M5 ;
      RECT 48.816000 0.000000 48.840000 0.084000 ;
    END
  END head_record[382]
  PIN head_record[383]
    DIRECTION INPUT ;
    USE SIGNAL ;
    PORT
      LAYER M5 ;
      RECT 49.248000 0.000000 49.272000 0.084000 ;
    END
  END head_record[383]
  PIN head_record[384]
    DIRECTION INPUT ;
    USE SIGNAL ;
    PORT
      LAYER M5 ;
      RECT 49.680000 0.000000 49.704000 0.084000 ;
    END
  END head_record[384]
  PIN head_record[385]
    DIRECTION INPUT ;
    USE SIGNAL ;
    PORT
      LAYER M5 ;
      RECT 50.112000 0.000000 50.136000 0.084000 ;
    END
  END head_record[385]
  PIN head_record[386]
    DIRECTION INPUT ;
    USE SIGNAL ;
    PORT
      LAYER M5 ;
      RECT 50.544000 0.000000 50.568000 0.084000 ;
    END
  END head_record[386]
  PIN head_record[387]
    DIRECTION INPUT ;
    USE SIGNAL ;
    PORT
      LAYER M5 ;
      RECT 50.976000 0.000000 51.000000 0.084000 ;
    END
  END head_record[387]
  PIN head_record[388]
    DIRECTION INPUT ;
    USE SIGNAL ;
    PORT
      LAYER M5 ;
      RECT 51.408000 0.000000 51.432000 0.084000 ;
    END
  END head_record[388]
  PIN head_record[389]
    DIRECTION INPUT ;
    USE SIGNAL ;
    PORT
      LAYER M5 ;
      RECT 51.840000 0.000000 51.864000 0.084000 ;
    END
  END head_record[389]
  PIN head_record[390]
    DIRECTION INPUT ;
    USE SIGNAL ;
    PORT
      LAYER M5 ;
      RECT 52.320000 0.000000 52.344000 0.084000 ;
    END
  END head_record[390]
  PIN head_record[391]
    DIRECTION INPUT ;
    USE SIGNAL ;
    PORT
      LAYER M5 ;
      RECT 52.752000 0.000000 52.776000 0.084000 ;
    END
  END head_record[391]
  PIN head_record[392]
    DIRECTION INPUT ;
    USE SIGNAL ;
    PORT
      LAYER M5 ;
      RECT 53.184000 0.000000 53.208000 0.084000 ;
    END
  END head_record[392]
  PIN head_record[393]
    DIRECTION INPUT ;
    USE SIGNAL ;
    PORT
      LAYER M5 ;
      RECT 53.616000 0.000000 53.640000 0.084000 ;
    END
  END head_record[393]
  PIN head_record[394]
    DIRECTION INPUT ;
    USE SIGNAL ;
    PORT
      LAYER M5 ;
      RECT 54.048000 0.000000 54.072000 0.084000 ;
    END
  END head_record[394]
  PIN head_record[395]
    DIRECTION INPUT ;
    USE SIGNAL ;
    PORT
      LAYER M5 ;
      RECT 54.480000 0.000000 54.504000 0.084000 ;
    END
  END head_record[395]
  PIN head_record[396]
    DIRECTION INPUT ;
    USE SIGNAL ;
    PORT
      LAYER M5 ;
      RECT 54.912000 0.000000 54.936000 0.084000 ;
    END
  END head_record[396]
  PIN head_record[397]
    DIRECTION INPUT ;
    USE SIGNAL ;
    PORT
      LAYER M5 ;
      RECT 55.344000 0.000000 55.368000 0.084000 ;
    END
  END head_record[397]
  PIN head_record[398]
    DIRECTION INPUT ;
    USE SIGNAL ;
    PORT
      LAYER M5 ;
      RECT 55.776000 0.000000 55.800000 0.084000 ;
    END
  END head_record[398]
  PIN head_record[399]
    DIRECTION INPUT ;
    USE SIGNAL ;
    PORT
      LAYER M5 ;
      RECT 56.256000 0.000000 56.280000 0.084000 ;
    END
  END head_record[399]
  PIN head_record[400]
    DIRECTION INPUT ;
    USE SIGNAL ;
    PORT
      LAYER M5 ;
      RECT 56.688000 0.000000 56.712000 0.084000 ;
    END
  END head_record[400]
  PIN head_record[401]
    DIRECTION INPUT ;
    USE SIGNAL ;
    PORT
      LAYER M5 ;
      RECT 57.120000 0.000000 57.144000 0.084000 ;
    END
  END head_record[401]
  PIN head_record[402]
    DIRECTION INPUT ;
    USE SIGNAL ;
    PORT
      LAYER M5 ;
      RECT 57.552000 0.000000 57.576000 0.084000 ;
    END
  END head_record[402]
  PIN head_record[403]
    DIRECTION INPUT ;
    USE SIGNAL ;
    PORT
      LAYER M5 ;
      RECT 57.984000 0.000000 58.008000 0.084000 ;
    END
  END head_record[403]
  PIN head_record[404]
    DIRECTION INPUT ;
    USE SIGNAL ;
    PORT
      LAYER M5 ;
      RECT 58.416000 0.000000 58.440000 0.084000 ;
    END
  END head_record[404]
  PIN head_record[405]
    DIRECTION INPUT ;
    USE SIGNAL ;
    PORT
      LAYER M5 ;
      RECT 58.848000 0.000000 58.872000 0.084000 ;
    END
  END head_record[405]
  PIN head_record[406]
    DIRECTION INPUT ;
    USE SIGNAL ;
    PORT
      LAYER M5 ;
      RECT 59.280000 0.000000 59.304000 0.084000 ;
    END
  END head_record[406]
  PIN head_record[407]
    DIRECTION INPUT ;
    USE SIGNAL ;
    PORT
      LAYER M5 ;
      RECT 59.712000 0.000000 59.736000 0.084000 ;
    END
  END head_record[407]
  PIN head_record[408]
    DIRECTION INPUT ;
    USE SIGNAL ;
    PORT
      LAYER M5 ;
      RECT 60.192000 0.000000 60.216000 0.084000 ;
    END
  END head_record[408]
  PIN head_record[409]
    DIRECTION INPUT ;
    USE SIGNAL ;
    PORT
      LAYER M5 ;
      RECT 60.624000 0.000000 60.648000 0.084000 ;
    END
  END head_record[409]
  PIN head_record[410]
    DIRECTION INPUT ;
    USE SIGNAL ;
    PORT
      LAYER M5 ;
      RECT 61.056000 0.000000 61.080000 0.084000 ;
    END
  END head_record[410]
  PIN head_record[411]
    DIRECTION INPUT ;
    USE SIGNAL ;
    PORT
      LAYER M5 ;
      RECT 61.488000 0.000000 61.512000 0.084000 ;
    END
  END head_record[411]
  PIN head_record[412]
    DIRECTION INPUT ;
    USE SIGNAL ;
    PORT
      LAYER M5 ;
      RECT 61.920000 0.000000 61.944000 0.084000 ;
    END
  END head_record[412]
  PIN head_record[413]
    DIRECTION INPUT ;
    USE SIGNAL ;
    PORT
      LAYER M5 ;
      RECT 62.352000 0.000000 62.376000 0.084000 ;
    END
  END head_record[413]
  PIN head_record[414]
    DIRECTION INPUT ;
    USE SIGNAL ;
    PORT
      LAYER M4 ;
      RECT 64.716000 2.352000 64.800000 2.376000 ;
    END
  END head_record[414]
  PIN head_record[415]
    DIRECTION INPUT ;
    USE SIGNAL ;
    PORT
      LAYER M4 ;
      RECT 64.716000 2.640000 64.800000 2.664000 ;
    END
  END head_record[415]
  PIN head_record[416]
    DIRECTION INPUT ;
    USE SIGNAL ;
    PORT
      LAYER M4 ;
      RECT 64.716000 2.928000 64.800000 2.952000 ;
    END
  END head_record[416]
  PIN head_record[417]
    DIRECTION INPUT ;
    USE SIGNAL ;
    PORT
      LAYER M4 ;
      RECT 64.716000 3.264000 64.800000 3.288000 ;
    END
  END head_record[417]
  PIN head_record[418]
    DIRECTION INPUT ;
    USE SIGNAL ;
    PORT
      LAYER M4 ;
      RECT 64.716000 3.552000 64.800000 3.576000 ;
    END
  END head_record[418]
  PIN head_record[419]
    DIRECTION INPUT ;
    USE SIGNAL ;
    PORT
      LAYER M4 ;
      RECT 64.716000 3.840000 64.800000 3.864000 ;
    END
  END head_record[419]
  PIN head_record[420]
    DIRECTION INPUT ;
    USE SIGNAL ;
    PORT
      LAYER M4 ;
      RECT 64.716000 4.176000 64.800000 4.200000 ;
    END
  END head_record[420]
  PIN head_record[421]
    DIRECTION INPUT ;
    USE SIGNAL ;
    PORT
      LAYER M4 ;
      RECT 64.716000 4.464000 64.800000 4.488000 ;
    END
  END head_record[421]
  PIN head_record[422]
    DIRECTION INPUT ;
    USE SIGNAL ;
    PORT
      LAYER M4 ;
      RECT 64.716000 4.752000 64.800000 4.776000 ;
    END
  END head_record[422]
  PIN head_record[423]
    DIRECTION INPUT ;
    USE SIGNAL ;
    PORT
      LAYER M4 ;
      RECT 64.716000 5.088000 64.800000 5.112000 ;
    END
  END head_record[423]
  PIN head_record[424]
    DIRECTION INPUT ;
    USE SIGNAL ;
    PORT
      LAYER M4 ;
      RECT 64.716000 5.376000 64.800000 5.400000 ;
    END
  END head_record[424]
  PIN head_record[425]
    DIRECTION INPUT ;
    USE SIGNAL ;
    PORT
      LAYER M4 ;
      RECT 64.716000 5.664000 64.800000 5.688000 ;
    END
  END head_record[425]
  PIN head_record[426]
    DIRECTION INPUT ;
    USE SIGNAL ;
    PORT
      LAYER M4 ;
      RECT 64.716000 5.952000 64.800000 5.976000 ;
    END
  END head_record[426]
  PIN head_record[427]
    DIRECTION INPUT ;
    USE SIGNAL ;
    PORT
      LAYER M4 ;
      RECT 64.716000 6.288000 64.800000 6.312000 ;
    END
  END head_record[427]
  PIN head_record[428]
    DIRECTION INPUT ;
    USE SIGNAL ;
    PORT
      LAYER M4 ;
      RECT 64.716000 6.576000 64.800000 6.600000 ;
    END
  END head_record[428]
  PIN head_record[429]
    DIRECTION INPUT ;
    USE SIGNAL ;
    PORT
      LAYER M4 ;
      RECT 64.716000 6.864000 64.800000 6.888000 ;
    END
  END head_record[429]
  PIN head_record[430]
    DIRECTION INPUT ;
    USE SIGNAL ;
    PORT
      LAYER M4 ;
      RECT 64.716000 7.200000 64.800000 7.224000 ;
    END
  END head_record[430]
  PIN head_record[431]
    DIRECTION INPUT ;
    USE SIGNAL ;
    PORT
      LAYER M4 ;
      RECT 64.716000 7.488000 64.800000 7.512000 ;
    END
  END head_record[431]
  PIN head_record[432]
    DIRECTION INPUT ;
    USE SIGNAL ;
    PORT
      LAYER M4 ;
      RECT 64.716000 7.776000 64.800000 7.800000 ;
    END
  END head_record[432]
  PIN head_record[433]
    DIRECTION INPUT ;
    USE SIGNAL ;
    PORT
      LAYER M4 ;
      RECT 64.716000 8.064000 64.800000 8.088000 ;
    END
  END head_record[433]
  PIN head_record[434]
    DIRECTION INPUT ;
    USE SIGNAL ;
    PORT
      LAYER M4 ;
      RECT 64.716000 8.400000 64.800000 8.424000 ;
    END
  END head_record[434]
  PIN head_record[435]
    DIRECTION INPUT ;
    USE SIGNAL ;
    PORT
      LAYER M4 ;
      RECT 64.716000 8.688000 64.800000 8.712000 ;
    END
  END head_record[435]
  PIN head_record[436]
    DIRECTION INPUT ;
    USE SIGNAL ;
    PORT
      LAYER M4 ;
      RECT 64.716000 8.976000 64.800000 9.000000 ;
    END
  END head_record[436]
  PIN head_record[437]
    DIRECTION INPUT ;
    USE SIGNAL ;
    PORT
      LAYER M4 ;
      RECT 64.716000 9.312000 64.800000 9.336000 ;
    END
  END head_record[437]
  PIN head_record[438]
    DIRECTION INPUT ;
    USE SIGNAL ;
    PORT
      LAYER M4 ;
      RECT 64.716000 9.600000 64.800000 9.624000 ;
    END
  END head_record[438]
  PIN head_record[439]
    DIRECTION INPUT ;
    USE SIGNAL ;
    PORT
      LAYER M4 ;
      RECT 64.716000 9.888000 64.800000 9.912000 ;
    END
  END head_record[439]
  PIN head_record[440]
    DIRECTION INPUT ;
    USE SIGNAL ;
    PORT
      LAYER M4 ;
      RECT 64.716000 10.176000 64.800000 10.200000 ;
    END
  END head_record[440]
  PIN head_record[441]
    DIRECTION INPUT ;
    USE SIGNAL ;
    PORT
      LAYER M4 ;
      RECT 64.716000 10.512000 64.800000 10.536000 ;
    END
  END head_record[441]
  PIN head_record[442]
    DIRECTION INPUT ;
    USE SIGNAL ;
    PORT
      LAYER M4 ;
      RECT 64.716000 10.800000 64.800000 10.824000 ;
    END
  END head_record[442]
  PIN head_record[443]
    DIRECTION INPUT ;
    USE SIGNAL ;
    PORT
      LAYER M4 ;
      RECT 64.716000 11.088000 64.800000 11.112000 ;
    END
  END head_record[443]
  PIN head_record[444]
    DIRECTION INPUT ;
    USE SIGNAL ;
    PORT
      LAYER M4 ;
      RECT 64.716000 11.424000 64.800000 11.448000 ;
    END
  END head_record[444]
  PIN head_record[445]
    DIRECTION INPUT ;
    USE SIGNAL ;
    PORT
      LAYER M4 ;
      RECT 64.716000 11.712000 64.800000 11.736000 ;
    END
  END head_record[445]
  PIN head_record[446]
    DIRECTION INPUT ;
    USE SIGNAL ;
    PORT
      LAYER M4 ;
      RECT 64.716000 12.000000 64.800000 12.024000 ;
    END
  END head_record[446]
  PIN head_record[447]
    DIRECTION INPUT ;
    USE SIGNAL ;
    PORT
      LAYER M4 ;
      RECT 64.716000 12.288000 64.800000 12.312000 ;
    END
  END head_record[447]
  PIN head_record[448]
    DIRECTION INPUT ;
    USE SIGNAL ;
    PORT
      LAYER M4 ;
      RECT 64.716000 12.624000 64.800000 12.648000 ;
    END
  END head_record[448]
  PIN head_record[449]
    DIRECTION INPUT ;
    USE SIGNAL ;
    PORT
      LAYER M4 ;
      RECT 64.716000 12.912000 64.800000 12.936000 ;
    END
  END head_record[449]
  PIN head_record[450]
    DIRECTION INPUT ;
    USE SIGNAL ;
    PORT
      LAYER M4 ;
      RECT 64.716000 13.200000 64.800000 13.224000 ;
    END
  END head_record[450]
  PIN head_record[451]
    DIRECTION INPUT ;
    USE SIGNAL ;
    PORT
      LAYER M4 ;
      RECT 64.716000 13.536000 64.800000 13.560000 ;
    END
  END head_record[451]
  PIN head_record[452]
    DIRECTION INPUT ;
    USE SIGNAL ;
    PORT
      LAYER M4 ;
      RECT 64.716000 13.824000 64.800000 13.848000 ;
    END
  END head_record[452]
  PIN head_record[453]
    DIRECTION INPUT ;
    USE SIGNAL ;
    PORT
      LAYER M4 ;
      RECT 64.716000 14.112000 64.800000 14.136000 ;
    END
  END head_record[453]
  PIN head_record[454]
    DIRECTION INPUT ;
    USE SIGNAL ;
    PORT
      LAYER M4 ;
      RECT 64.716000 14.400000 64.800000 14.424000 ;
    END
  END head_record[454]
  PIN head_record[455]
    DIRECTION INPUT ;
    USE SIGNAL ;
    PORT
      LAYER M4 ;
      RECT 64.716000 14.736000 64.800000 14.760000 ;
    END
  END head_record[455]
  PIN head_record[456]
    DIRECTION INPUT ;
    USE SIGNAL ;
    PORT
      LAYER M4 ;
      RECT 64.716000 15.024000 64.800000 15.048000 ;
    END
  END head_record[456]
  PIN head_record[457]
    DIRECTION INPUT ;
    USE SIGNAL ;
    PORT
      LAYER M4 ;
      RECT 64.716000 15.312000 64.800000 15.336000 ;
    END
  END head_record[457]
  PIN head_record[458]
    DIRECTION INPUT ;
    USE SIGNAL ;
    PORT
      LAYER M4 ;
      RECT 64.716000 15.648000 64.800000 15.672000 ;
    END
  END head_record[458]
  PIN head_record[459]
    DIRECTION INPUT ;
    USE SIGNAL ;
    PORT
      LAYER M4 ;
      RECT 64.716000 15.936000 64.800000 15.960000 ;
    END
  END head_record[459]
  PIN head_record[460]
    DIRECTION INPUT ;
    USE SIGNAL ;
    PORT
      LAYER M4 ;
      RECT 64.716000 16.224000 64.800000 16.248000 ;
    END
  END head_record[460]
  PIN head_record[461]
    DIRECTION INPUT ;
    USE SIGNAL ;
    PORT
      LAYER M4 ;
      RECT 64.716000 16.560000 64.800000 16.584000 ;
    END
  END head_record[461]
  PIN head_record[462]
    DIRECTION INPUT ;
    USE SIGNAL ;
    PORT
      LAYER M4 ;
      RECT 64.716000 16.848000 64.800000 16.872000 ;
    END
  END head_record[462]
  PIN head_record[463]
    DIRECTION INPUT ;
    USE SIGNAL ;
    PORT
      LAYER M4 ;
      RECT 64.716000 17.136000 64.800000 17.160000 ;
    END
  END head_record[463]
  PIN head_record[464]
    DIRECTION INPUT ;
    USE SIGNAL ;
    PORT
      LAYER M4 ;
      RECT 64.716000 17.424000 64.800000 17.448000 ;
    END
  END head_record[464]
  PIN head_record[465]
    DIRECTION INPUT ;
    USE SIGNAL ;
    PORT
      LAYER M4 ;
      RECT 64.716000 17.760000 64.800000 17.784000 ;
    END
  END head_record[465]
  PIN head_record[466]
    DIRECTION INPUT ;
    USE SIGNAL ;
    PORT
      LAYER M4 ;
      RECT 64.716000 18.048000 64.800000 18.072000 ;
    END
  END head_record[466]
  PIN head_record[467]
    DIRECTION INPUT ;
    USE SIGNAL ;
    PORT
      LAYER M4 ;
      RECT 64.716000 18.336000 64.800000 18.360000 ;
    END
  END head_record[467]
  PIN head_record[468]
    DIRECTION INPUT ;
    USE SIGNAL ;
    PORT
      LAYER M4 ;
      RECT 64.716000 18.672000 64.800000 18.696000 ;
    END
  END head_record[468]
  PIN head_record[469]
    DIRECTION INPUT ;
    USE SIGNAL ;
    PORT
      LAYER M4 ;
      RECT 64.716000 18.960000 64.800000 18.984000 ;
    END
  END head_record[469]
  PIN head_record[470]
    DIRECTION INPUT ;
    USE SIGNAL ;
    PORT
      LAYER M4 ;
      RECT 64.716000 19.248000 64.800000 19.272000 ;
    END
  END head_record[470]
  PIN head_record[471]
    DIRECTION INPUT ;
    USE SIGNAL ;
    PORT
      LAYER M4 ;
      RECT 64.716000 19.536000 64.800000 19.560000 ;
    END
  END head_record[471]
  PIN head_record[472]
    DIRECTION INPUT ;
    USE SIGNAL ;
    PORT
      LAYER M4 ;
      RECT 64.716000 19.872000 64.800000 19.896000 ;
    END
  END head_record[472]
  PIN head_record[473]
    DIRECTION INPUT ;
    USE SIGNAL ;
    PORT
      LAYER M4 ;
      RECT 64.716000 20.160000 64.800000 20.184000 ;
    END
  END head_record[473]
  PIN head_record[474]
    DIRECTION INPUT ;
    USE SIGNAL ;
    PORT
      LAYER M4 ;
      RECT 64.716000 20.448000 64.800000 20.472000 ;
    END
  END head_record[474]
  PIN head_record[475]
    DIRECTION INPUT ;
    USE SIGNAL ;
    PORT
      LAYER M4 ;
      RECT 64.716000 20.784000 64.800000 20.808000 ;
    END
  END head_record[475]
  PIN head_record[476]
    DIRECTION INPUT ;
    USE SIGNAL ;
    PORT
      LAYER M4 ;
      RECT 64.716000 21.072000 64.800000 21.096000 ;
    END
  END head_record[476]
  PIN head_record[477]
    DIRECTION INPUT ;
    USE SIGNAL ;
    PORT
      LAYER M4 ;
      RECT 64.716000 21.360000 64.800000 21.384000 ;
    END
  END head_record[477]
  PIN head_record[478]
    DIRECTION INPUT ;
    USE SIGNAL ;
    PORT
      LAYER M4 ;
      RECT 64.716000 21.648000 64.800000 21.672000 ;
    END
  END head_record[478]
  PIN head_record[479]
    DIRECTION INPUT ;
    USE SIGNAL ;
    PORT
      LAYER M4 ;
      RECT 64.716000 21.984000 64.800000 22.008000 ;
    END
  END head_record[479]
  PIN head_record[480]
    DIRECTION INPUT ;
    USE SIGNAL ;
    PORT
      LAYER M4 ;
      RECT 64.716000 22.272000 64.800000 22.296000 ;
    END
  END head_record[480]
  PIN head_record[481]
    DIRECTION INPUT ;
    USE SIGNAL ;
    PORT
      LAYER M4 ;
      RECT 64.716000 22.560000 64.800000 22.584000 ;
    END
  END head_record[481]
  PIN head_record[482]
    DIRECTION INPUT ;
    USE SIGNAL ;
    PORT
      LAYER M4 ;
      RECT 64.716000 22.896000 64.800000 22.920000 ;
    END
  END head_record[482]
  PIN head_record[483]
    DIRECTION INPUT ;
    USE SIGNAL ;
    PORT
      LAYER M4 ;
      RECT 64.716000 23.184000 64.800000 23.208000 ;
    END
  END head_record[483]
  PIN head_record[484]
    DIRECTION INPUT ;
    USE SIGNAL ;
    PORT
      LAYER M4 ;
      RECT 64.716000 23.472000 64.800000 23.496000 ;
    END
  END head_record[484]
  PIN head_record[485]
    DIRECTION INPUT ;
    USE SIGNAL ;
    PORT
      LAYER M4 ;
      RECT 64.716000 23.760000 64.800000 23.784000 ;
    END
  END head_record[485]
  PIN head_record[486]
    DIRECTION INPUT ;
    USE SIGNAL ;
    PORT
      LAYER M4 ;
      RECT 64.716000 24.096000 64.800000 24.120000 ;
    END
  END head_record[486]
  PIN head_record[487]
    DIRECTION INPUT ;
    USE SIGNAL ;
    PORT
      LAYER M4 ;
      RECT 64.716000 24.384000 64.800000 24.408000 ;
    END
  END head_record[487]
  PIN head_record[488]
    DIRECTION INPUT ;
    USE SIGNAL ;
    PORT
      LAYER M4 ;
      RECT 64.716000 24.672000 64.800000 24.696000 ;
    END
  END head_record[488]
  PIN head_record[489]
    DIRECTION INPUT ;
    USE SIGNAL ;
    PORT
      LAYER M4 ;
      RECT 64.716000 25.008000 64.800000 25.032000 ;
    END
  END head_record[489]
  PIN head_record[490]
    DIRECTION INPUT ;
    USE SIGNAL ;
    PORT
      LAYER M4 ;
      RECT 64.716000 25.296000 64.800000 25.320000 ;
    END
  END head_record[490]
  PIN head_record[491]
    DIRECTION INPUT ;
    USE SIGNAL ;
    PORT
      LAYER M4 ;
      RECT 64.716000 25.584000 64.800000 25.608000 ;
    END
  END head_record[491]
  PIN head_record[492]
    DIRECTION INPUT ;
    USE SIGNAL ;
    PORT
      LAYER M4 ;
      RECT 64.716000 25.920000 64.800000 25.944000 ;
    END
  END head_record[492]
  PIN head_record[493]
    DIRECTION INPUT ;
    USE SIGNAL ;
    PORT
      LAYER M4 ;
      RECT 64.716000 26.208000 64.800000 26.232000 ;
    END
  END head_record[493]
  PIN head_record[494]
    DIRECTION INPUT ;
    USE SIGNAL ;
    PORT
      LAYER M4 ;
      RECT 64.716000 26.496000 64.800000 26.520000 ;
    END
  END head_record[494]
  PIN head_record[495]
    DIRECTION INPUT ;
    USE SIGNAL ;
    PORT
      LAYER M4 ;
      RECT 64.716000 26.784000 64.800000 26.808000 ;
    END
  END head_record[495]
  PIN head_record[496]
    DIRECTION INPUT ;
    USE SIGNAL ;
    PORT
      LAYER M4 ;
      RECT 64.716000 27.120000 64.800000 27.144000 ;
    END
  END head_record[496]
  PIN head_record[497]
    DIRECTION INPUT ;
    USE SIGNAL ;
    PORT
      LAYER M4 ;
      RECT 64.716000 27.408000 64.800000 27.432000 ;
    END
  END head_record[497]
  PIN head_record[498]
    DIRECTION INPUT ;
    USE SIGNAL ;
    PORT
      LAYER M4 ;
      RECT 64.716000 27.696000 64.800000 27.720000 ;
    END
  END head_record[498]
  PIN head_record[499]
    DIRECTION INPUT ;
    USE SIGNAL ;
    PORT
      LAYER M4 ;
      RECT 64.716000 28.032000 64.800000 28.056000 ;
    END
  END head_record[499]
  PIN head_record[500]
    DIRECTION INPUT ;
    USE SIGNAL ;
    PORT
      LAYER M4 ;
      RECT 64.716000 28.320000 64.800000 28.344000 ;
    END
  END head_record[500]
  PIN head_record[501]
    DIRECTION INPUT ;
    USE SIGNAL ;
    PORT
      LAYER M4 ;
      RECT 64.716000 28.608000 64.800000 28.632000 ;
    END
  END head_record[501]
  PIN head_record[502]
    DIRECTION INPUT ;
    USE SIGNAL ;
    PORT
      LAYER M4 ;
      RECT 64.716000 28.896000 64.800000 28.920000 ;
    END
  END head_record[502]
  PIN head_record[503]
    DIRECTION INPUT ;
    USE SIGNAL ;
    PORT
      LAYER M4 ;
      RECT 64.716000 29.232000 64.800000 29.256000 ;
    END
  END head_record[503]
  PIN head_record[504]
    DIRECTION INPUT ;
    USE SIGNAL ;
    PORT
      LAYER M4 ;
      RECT 64.716000 29.520000 64.800000 29.544000 ;
    END
  END head_record[504]
  PIN head_record[505]
    DIRECTION INPUT ;
    USE SIGNAL ;
    PORT
      LAYER M4 ;
      RECT 64.716000 29.808000 64.800000 29.832000 ;
    END
  END head_record[505]
  PIN head_record[506]
    DIRECTION INPUT ;
    USE SIGNAL ;
    PORT
      LAYER M4 ;
      RECT 64.716000 30.144000 64.800000 30.168000 ;
    END
  END head_record[506]
  PIN head_record[507]
    DIRECTION INPUT ;
    USE SIGNAL ;
    PORT
      LAYER M4 ;
      RECT 64.716000 30.432000 64.800000 30.456000 ;
    END
  END head_record[507]
  PIN head_record[508]
    DIRECTION INPUT ;
    USE SIGNAL ;
    PORT
      LAYER M4 ;
      RECT 64.716000 30.720000 64.800000 30.744000 ;
    END
  END head_record[508]
  PIN head_record[509]
    DIRECTION INPUT ;
    USE SIGNAL ;
    PORT
      LAYER M4 ;
      RECT 64.716000 31.008000 64.800000 31.032000 ;
    END
  END head_record[509]
  PIN head_record[510]
    DIRECTION INPUT ;
    USE SIGNAL ;
    PORT
      LAYER M4 ;
      RECT 64.716000 31.344000 64.800000 31.368000 ;
    END
  END head_record[510]
  PIN head_record[511]
    DIRECTION INPUT ;
    USE SIGNAL ;
    PORT
      LAYER M4 ;
      RECT 64.716000 31.632000 64.800000 31.656000 ;
    END
  END head_record[511]
  PIN head_record[512]
    DIRECTION INPUT ;
    USE SIGNAL ;
    PORT
      LAYER M4 ;
      RECT 64.716000 31.920000 64.800000 31.944000 ;
    END
  END head_record[512]
  PIN head_record[513]
    DIRECTION INPUT ;
    USE SIGNAL ;
    PORT
      LAYER M4 ;
      RECT 64.716000 32.256000 64.800000 32.280000 ;
    END
  END head_record[513]
  PIN head_record[514]
    DIRECTION INPUT ;
    USE SIGNAL ;
    PORT
      LAYER M4 ;
      RECT 64.716000 32.544000 64.800000 32.568000 ;
    END
  END head_record[514]
  PIN head_record[515]
    DIRECTION INPUT ;
    USE SIGNAL ;
    PORT
      LAYER M4 ;
      RECT 64.716000 32.832000 64.800000 32.856000 ;
    END
  END head_record[515]
  PIN head_record[516]
    DIRECTION INPUT ;
    USE SIGNAL ;
    PORT
      LAYER M4 ;
      RECT 64.716000 33.120000 64.800000 33.144000 ;
    END
  END head_record[516]
  PIN head_record[517]
    DIRECTION INPUT ;
    USE SIGNAL ;
    PORT
      LAYER M4 ;
      RECT 64.716000 33.456000 64.800000 33.480000 ;
    END
  END head_record[517]
  PIN head_record[518]
    DIRECTION INPUT ;
    USE SIGNAL ;
    PORT
      LAYER M4 ;
      RECT 64.716000 33.744000 64.800000 33.768000 ;
    END
  END head_record[518]
  PIN head_record[519]
    DIRECTION INPUT ;
    USE SIGNAL ;
    PORT
      LAYER M4 ;
      RECT 64.716000 34.032000 64.800000 34.056000 ;
    END
  END head_record[519]
  PIN head_record[520]
    DIRECTION INPUT ;
    USE SIGNAL ;
    PORT
      LAYER M4 ;
      RECT 64.716000 34.368000 64.800000 34.392000 ;
    END
  END head_record[520]
  PIN head_record[521]
    DIRECTION INPUT ;
    USE SIGNAL ;
    PORT
      LAYER M4 ;
      RECT 64.716000 34.656000 64.800000 34.680000 ;
    END
  END head_record[521]
  PIN head_record[522]
    DIRECTION INPUT ;
    USE SIGNAL ;
    PORT
      LAYER M4 ;
      RECT 64.716000 34.944000 64.800000 34.968000 ;
    END
  END head_record[522]
  PIN head_record[523]
    DIRECTION INPUT ;
    USE SIGNAL ;
    PORT
      LAYER M4 ;
      RECT 64.716000 35.280000 64.800000 35.304000 ;
    END
  END head_record[523]
  PIN head_record[524]
    DIRECTION INPUT ;
    USE SIGNAL ;
    PORT
      LAYER M4 ;
      RECT 64.716000 35.568000 64.800000 35.592000 ;
    END
  END head_record[524]
  PIN head_record[525]
    DIRECTION INPUT ;
    USE SIGNAL ;
    PORT
      LAYER M4 ;
      RECT 64.716000 35.856000 64.800000 35.880000 ;
    END
  END head_record[525]
  PIN head_record[526]
    DIRECTION INPUT ;
    USE SIGNAL ;
    PORT
      LAYER M4 ;
      RECT 64.716000 36.144000 64.800000 36.168000 ;
    END
  END head_record[526]
  PIN head_record[527]
    DIRECTION INPUT ;
    USE SIGNAL ;
    PORT
      LAYER M4 ;
      RECT 64.716000 36.480000 64.800000 36.504000 ;
    END
  END head_record[527]
  PIN head_record[528]
    DIRECTION INPUT ;
    USE SIGNAL ;
    PORT
      LAYER M4 ;
      RECT 64.716000 36.768000 64.800000 36.792000 ;
    END
  END head_record[528]
  PIN head_record[529]
    DIRECTION INPUT ;
    USE SIGNAL ;
    PORT
      LAYER M4 ;
      RECT 64.716000 37.056000 64.800000 37.080000 ;
    END
  END head_record[529]
  PIN head_record[530]
    DIRECTION INPUT ;
    USE SIGNAL ;
    PORT
      LAYER M4 ;
      RECT 64.716000 37.392000 64.800000 37.416000 ;
    END
  END head_record[530]
  PIN head_record[531]
    DIRECTION INPUT ;
    USE SIGNAL ;
    PORT
      LAYER M4 ;
      RECT 64.716000 37.680000 64.800000 37.704000 ;
    END
  END head_record[531]
  PIN head_record[532]
    DIRECTION INPUT ;
    USE SIGNAL ;
    PORT
      LAYER M4 ;
      RECT 64.716000 37.968000 64.800000 37.992000 ;
    END
  END head_record[532]
  PIN head_record[533]
    DIRECTION INPUT ;
    USE SIGNAL ;
    PORT
      LAYER M4 ;
      RECT 64.716000 38.256000 64.800000 38.280000 ;
    END
  END head_record[533]
  PIN head_record[534]
    DIRECTION INPUT ;
    USE SIGNAL ;
    PORT
      LAYER M4 ;
      RECT 64.716000 38.592000 64.800000 38.616000 ;
    END
  END head_record[534]
  PIN head_record[535]
    DIRECTION INPUT ;
    USE SIGNAL ;
    PORT
      LAYER M4 ;
      RECT 64.716000 38.880000 64.800000 38.904000 ;
    END
  END head_record[535]
  PIN head_record[536]
    DIRECTION INPUT ;
    USE SIGNAL ;
    PORT
      LAYER M4 ;
      RECT 64.716000 39.168000 64.800000 39.192000 ;
    END
  END head_record[536]
  PIN head_record[537]
    DIRECTION INPUT ;
    USE SIGNAL ;
    PORT
      LAYER M4 ;
      RECT 64.716000 39.504000 64.800000 39.528000 ;
    END
  END head_record[537]
  PIN head_record[538]
    DIRECTION INPUT ;
    USE SIGNAL ;
    PORT
      LAYER M4 ;
      RECT 64.716000 39.792000 64.800000 39.816000 ;
    END
  END head_record[538]
  PIN head_record[539]
    DIRECTION INPUT ;
    USE SIGNAL ;
    PORT
      LAYER M4 ;
      RECT 64.716000 40.080000 64.800000 40.104000 ;
    END
  END head_record[539]
  PIN head_record[540]
    DIRECTION INPUT ;
    USE SIGNAL ;
    PORT
      LAYER M4 ;
      RECT 64.716000 40.368000 64.800000 40.392000 ;
    END
  END head_record[540]
  PIN head_record[541]
    DIRECTION INPUT ;
    USE SIGNAL ;
    PORT
      LAYER M4 ;
      RECT 64.716000 40.704000 64.800000 40.728000 ;
    END
  END head_record[541]
  PIN head_record[542]
    DIRECTION INPUT ;
    USE SIGNAL ;
    PORT
      LAYER M4 ;
      RECT 64.716000 40.992000 64.800000 41.016000 ;
    END
  END head_record[542]
  PIN head_record[543]
    DIRECTION INPUT ;
    USE SIGNAL ;
    PORT
      LAYER M4 ;
      RECT 64.716000 41.280000 64.800000 41.304000 ;
    END
  END head_record[543]
  PIN head_record[544]
    DIRECTION INPUT ;
    USE SIGNAL ;
    PORT
      LAYER M4 ;
      RECT 64.716000 41.616000 64.800000 41.640000 ;
    END
  END head_record[544]
  PIN head_record[545]
    DIRECTION INPUT ;
    USE SIGNAL ;
    PORT
      LAYER M4 ;
      RECT 64.716000 41.904000 64.800000 41.928000 ;
    END
  END head_record[545]
  PIN head_record[546]
    DIRECTION INPUT ;
    USE SIGNAL ;
    PORT
      LAYER M4 ;
      RECT 64.716000 42.192000 64.800000 42.216000 ;
    END
  END head_record[546]
  PIN head_record[547]
    DIRECTION INPUT ;
    USE SIGNAL ;
    PORT
      LAYER M4 ;
      RECT 64.716000 42.480000 64.800000 42.504000 ;
    END
  END head_record[547]
  PIN head_record[548]
    DIRECTION INPUT ;
    USE SIGNAL ;
    PORT
      LAYER M4 ;
      RECT 64.716000 42.816000 64.800000 42.840000 ;
    END
  END head_record[548]
  PIN head_record[549]
    DIRECTION INPUT ;
    USE SIGNAL ;
    PORT
      LAYER M4 ;
      RECT 64.716000 43.104000 64.800000 43.128000 ;
    END
  END head_record[549]
  PIN head_record[550]
    DIRECTION INPUT ;
    USE SIGNAL ;
    PORT
      LAYER M4 ;
      RECT 64.716000 43.392000 64.800000 43.416000 ;
    END
  END head_record[550]
  PIN head_record[551]
    DIRECTION INPUT ;
    USE SIGNAL ;
    PORT
      LAYER M4 ;
      RECT 64.716000 43.728000 64.800000 43.752000 ;
    END
  END head_record[551]
  PIN compiled_identity[0]
    DIRECTION OUTPUT ;
    USE SIGNAL ;
    PORT
      LAYER M4 ;
      RECT 64.716000 44.016000 64.800000 44.040000 ;
    END
  END compiled_identity[0]
  PIN compiled_identity[1]
    DIRECTION OUTPUT ;
    USE SIGNAL ;
    PORT
      LAYER M4 ;
      RECT 64.716000 44.304000 64.800000 44.328000 ;
    END
  END compiled_identity[1]
  PIN compiled_identity[2]
    DIRECTION OUTPUT ;
    USE SIGNAL ;
    PORT
      LAYER M4 ;
      RECT 64.716000 44.592000 64.800000 44.616000 ;
    END
  END compiled_identity[2]
  PIN compiled_identity[3]
    DIRECTION OUTPUT ;
    USE SIGNAL ;
    PORT
      LAYER M4 ;
      RECT 64.716000 44.928000 64.800000 44.952000 ;
    END
  END compiled_identity[3]
  PIN compiled_identity[4]
    DIRECTION OUTPUT ;
    USE SIGNAL ;
    PORT
      LAYER M4 ;
      RECT 64.716000 45.216000 64.800000 45.240000 ;
    END
  END compiled_identity[4]
  PIN compiled_identity[5]
    DIRECTION OUTPUT ;
    USE SIGNAL ;
    PORT
      LAYER M4 ;
      RECT 64.716000 45.504000 64.800000 45.528000 ;
    END
  END compiled_identity[5]
  PIN compiled_identity[6]
    DIRECTION OUTPUT ;
    USE SIGNAL ;
    PORT
      LAYER M4 ;
      RECT 64.716000 45.840000 64.800000 45.864000 ;
    END
  END compiled_identity[6]
  PIN compiled_identity[7]
    DIRECTION OUTPUT ;
    USE SIGNAL ;
    PORT
      LAYER M4 ;
      RECT 64.716000 46.128000 64.800000 46.152000 ;
    END
  END compiled_identity[7]
  PIN compiled_identity[8]
    DIRECTION OUTPUT ;
    USE SIGNAL ;
    PORT
      LAYER M4 ;
      RECT 64.716000 46.416000 64.800000 46.440000 ;
    END
  END compiled_identity[8]
  PIN compiled_identity[9]
    DIRECTION OUTPUT ;
    USE SIGNAL ;
    PORT
      LAYER M4 ;
      RECT 64.716000 46.752000 64.800000 46.776000 ;
    END
  END compiled_identity[9]
  PIN compiled_identity[10]
    DIRECTION OUTPUT ;
    USE SIGNAL ;
    PORT
      LAYER M4 ;
      RECT 64.716000 47.040000 64.800000 47.064000 ;
    END
  END compiled_identity[10]
  PIN compiled_identity[11]
    DIRECTION OUTPUT ;
    USE SIGNAL ;
    PORT
      LAYER M4 ;
      RECT 64.716000 47.328000 64.800000 47.352000 ;
    END
  END compiled_identity[11]
  PIN compiled_identity[12]
    DIRECTION OUTPUT ;
    USE SIGNAL ;
    PORT
      LAYER M4 ;
      RECT 64.716000 47.616000 64.800000 47.640000 ;
    END
  END compiled_identity[12]
  PIN compiled_identity[13]
    DIRECTION OUTPUT ;
    USE SIGNAL ;
    PORT
      LAYER M4 ;
      RECT 64.716000 47.952000 64.800000 47.976000 ;
    END
  END compiled_identity[13]
  PIN compiled_identity[14]
    DIRECTION OUTPUT ;
    USE SIGNAL ;
    PORT
      LAYER M4 ;
      RECT 64.716000 48.240000 64.800000 48.264000 ;
    END
  END compiled_identity[14]
  PIN compiled_identity[15]
    DIRECTION OUTPUT ;
    USE SIGNAL ;
    PORT
      LAYER M4 ;
      RECT 64.716000 48.528000 64.800000 48.552000 ;
    END
  END compiled_identity[15]
  PIN compiled_identity[16]
    DIRECTION OUTPUT ;
    USE SIGNAL ;
    PORT
      LAYER M4 ;
      RECT 64.716000 48.864000 64.800000 48.888000 ;
    END
  END compiled_identity[16]
  PIN compiled_identity[17]
    DIRECTION OUTPUT ;
    USE SIGNAL ;
    PORT
      LAYER M4 ;
      RECT 64.716000 49.152000 64.800000 49.176000 ;
    END
  END compiled_identity[17]
  PIN compiled_identity[18]
    DIRECTION OUTPUT ;
    USE SIGNAL ;
    PORT
      LAYER M4 ;
      RECT 64.716000 49.440000 64.800000 49.464000 ;
    END
  END compiled_identity[18]
  PIN compiled_identity[19]
    DIRECTION OUTPUT ;
    USE SIGNAL ;
    PORT
      LAYER M4 ;
      RECT 64.716000 49.728000 64.800000 49.752000 ;
    END
  END compiled_identity[19]
  PIN compiled_identity[20]
    DIRECTION OUTPUT ;
    USE SIGNAL ;
    PORT
      LAYER M4 ;
      RECT 64.716000 50.064000 64.800000 50.088000 ;
    END
  END compiled_identity[20]
  PIN compiled_identity[21]
    DIRECTION OUTPUT ;
    USE SIGNAL ;
    PORT
      LAYER M4 ;
      RECT 64.716000 50.352000 64.800000 50.376000 ;
    END
  END compiled_identity[21]
  PIN compiled_identity[22]
    DIRECTION OUTPUT ;
    USE SIGNAL ;
    PORT
      LAYER M4 ;
      RECT 64.716000 50.640000 64.800000 50.664000 ;
    END
  END compiled_identity[22]
  PIN compiled_identity[23]
    DIRECTION OUTPUT ;
    USE SIGNAL ;
    PORT
      LAYER M4 ;
      RECT 64.716000 50.976000 64.800000 51.000000 ;
    END
  END compiled_identity[23]
  PIN compiled_identity[24]
    DIRECTION OUTPUT ;
    USE SIGNAL ;
    PORT
      LAYER M4 ;
      RECT 64.716000 51.264000 64.800000 51.288000 ;
    END
  END compiled_identity[24]
  PIN compiled_identity[25]
    DIRECTION OUTPUT ;
    USE SIGNAL ;
    PORT
      LAYER M4 ;
      RECT 64.716000 51.552000 64.800000 51.576000 ;
    END
  END compiled_identity[25]
  PIN compiled_identity[26]
    DIRECTION OUTPUT ;
    USE SIGNAL ;
    PORT
      LAYER M4 ;
      RECT 64.716000 51.840000 64.800000 51.864000 ;
    END
  END compiled_identity[26]
  PIN compiled_identity[27]
    DIRECTION OUTPUT ;
    USE SIGNAL ;
    PORT
      LAYER M4 ;
      RECT 64.716000 52.176000 64.800000 52.200000 ;
    END
  END compiled_identity[27]
  PIN compiled_identity[28]
    DIRECTION OUTPUT ;
    USE SIGNAL ;
    PORT
      LAYER M4 ;
      RECT 64.716000 52.464000 64.800000 52.488000 ;
    END
  END compiled_identity[28]
  PIN compiled_identity[29]
    DIRECTION OUTPUT ;
    USE SIGNAL ;
    PORT
      LAYER M4 ;
      RECT 64.716000 52.752000 64.800000 52.776000 ;
    END
  END compiled_identity[29]
  PIN compiled_identity[30]
    DIRECTION OUTPUT ;
    USE SIGNAL ;
    PORT
      LAYER M4 ;
      RECT 64.716000 53.088000 64.800000 53.112000 ;
    END
  END compiled_identity[30]
  PIN compiled_identity[31]
    DIRECTION OUTPUT ;
    USE SIGNAL ;
    PORT
      LAYER M4 ;
      RECT 64.716000 53.376000 64.800000 53.400000 ;
    END
  END compiled_identity[31]
  PIN compiled_identity[32]
    DIRECTION OUTPUT ;
    USE SIGNAL ;
    PORT
      LAYER M4 ;
      RECT 64.716000 53.664000 64.800000 53.688000 ;
    END
  END compiled_identity[32]
  PIN compiled_identity[33]
    DIRECTION OUTPUT ;
    USE SIGNAL ;
    PORT
      LAYER M4 ;
      RECT 64.716000 53.952000 64.800000 53.976000 ;
    END
  END compiled_identity[33]
  PIN compiled_identity[34]
    DIRECTION OUTPUT ;
    USE SIGNAL ;
    PORT
      LAYER M4 ;
      RECT 64.716000 54.288000 64.800000 54.312000 ;
    END
  END compiled_identity[34]
  PIN compiled_identity[35]
    DIRECTION OUTPUT ;
    USE SIGNAL ;
    PORT
      LAYER M4 ;
      RECT 64.716000 54.576000 64.800000 54.600000 ;
    END
  END compiled_identity[35]
  PIN compiled_identity[36]
    DIRECTION OUTPUT ;
    USE SIGNAL ;
    PORT
      LAYER M4 ;
      RECT 64.716000 54.864000 64.800000 54.888000 ;
    END
  END compiled_identity[36]
  PIN compiled_identity[37]
    DIRECTION OUTPUT ;
    USE SIGNAL ;
    PORT
      LAYER M4 ;
      RECT 64.716000 55.200000 64.800000 55.224000 ;
    END
  END compiled_identity[37]
  PIN compiled_identity[38]
    DIRECTION OUTPUT ;
    USE SIGNAL ;
    PORT
      LAYER M4 ;
      RECT 64.716000 55.488000 64.800000 55.512000 ;
    END
  END compiled_identity[38]
  PIN compiled_identity[39]
    DIRECTION OUTPUT ;
    USE SIGNAL ;
    PORT
      LAYER M4 ;
      RECT 64.716000 55.776000 64.800000 55.800000 ;
    END
  END compiled_identity[39]
  PIN compiled_identity[40]
    DIRECTION OUTPUT ;
    USE SIGNAL ;
    PORT
      LAYER M4 ;
      RECT 64.716000 56.112000 64.800000 56.136000 ;
    END
  END compiled_identity[40]
  PIN compiled_identity[41]
    DIRECTION OUTPUT ;
    USE SIGNAL ;
    PORT
      LAYER M4 ;
      RECT 64.716000 56.400000 64.800000 56.424000 ;
    END
  END compiled_identity[41]
  PIN compiled_identity[42]
    DIRECTION OUTPUT ;
    USE SIGNAL ;
    PORT
      LAYER M4 ;
      RECT 64.716000 56.688000 64.800000 56.712000 ;
    END
  END compiled_identity[42]
  PIN compiled_identity[43]
    DIRECTION OUTPUT ;
    USE SIGNAL ;
    PORT
      LAYER M4 ;
      RECT 64.716000 56.976000 64.800000 57.000000 ;
    END
  END compiled_identity[43]
  PIN compiled_identity[44]
    DIRECTION OUTPUT ;
    USE SIGNAL ;
    PORT
      LAYER M4 ;
      RECT 64.716000 57.312000 64.800000 57.336000 ;
    END
  END compiled_identity[44]
  PIN compiled_identity[45]
    DIRECTION OUTPUT ;
    USE SIGNAL ;
    PORT
      LAYER M4 ;
      RECT 64.716000 57.600000 64.800000 57.624000 ;
    END
  END compiled_identity[45]
  PIN compiled_identity[46]
    DIRECTION OUTPUT ;
    USE SIGNAL ;
    PORT
      LAYER M4 ;
      RECT 64.716000 57.888000 64.800000 57.912000 ;
    END
  END compiled_identity[46]
  PIN compiled_identity[47]
    DIRECTION OUTPUT ;
    USE SIGNAL ;
    PORT
      LAYER M4 ;
      RECT 64.716000 58.224000 64.800000 58.248000 ;
    END
  END compiled_identity[47]
  PIN compiled_identity[48]
    DIRECTION OUTPUT ;
    USE SIGNAL ;
    PORT
      LAYER M4 ;
      RECT 64.716000 58.512000 64.800000 58.536000 ;
    END
  END compiled_identity[48]
  PIN compiled_identity[49]
    DIRECTION OUTPUT ;
    USE SIGNAL ;
    PORT
      LAYER M4 ;
      RECT 64.716000 58.800000 64.800000 58.824000 ;
    END
  END compiled_identity[49]
  PIN compiled_identity[50]
    DIRECTION OUTPUT ;
    USE SIGNAL ;
    PORT
      LAYER M4 ;
      RECT 64.716000 59.088000 64.800000 59.112000 ;
    END
  END compiled_identity[50]
  PIN compiled_identity[51]
    DIRECTION OUTPUT ;
    USE SIGNAL ;
    PORT
      LAYER M4 ;
      RECT 64.716000 59.424000 64.800000 59.448000 ;
    END
  END compiled_identity[51]
  PIN compiled_identity[52]
    DIRECTION OUTPUT ;
    USE SIGNAL ;
    PORT
      LAYER M4 ;
      RECT 64.716000 59.712000 64.800000 59.736000 ;
    END
  END compiled_identity[52]
  PIN compiled_identity[53]
    DIRECTION OUTPUT ;
    USE SIGNAL ;
    PORT
      LAYER M4 ;
      RECT 64.716000 60.000000 64.800000 60.024000 ;
    END
  END compiled_identity[53]
  PIN compiled_identity[54]
    DIRECTION OUTPUT ;
    USE SIGNAL ;
    PORT
      LAYER M4 ;
      RECT 64.716000 60.336000 64.800000 60.360000 ;
    END
  END compiled_identity[54]
  PIN compiled_identity[55]
    DIRECTION OUTPUT ;
    USE SIGNAL ;
    PORT
      LAYER M4 ;
      RECT 64.716000 60.624000 64.800000 60.648000 ;
    END
  END compiled_identity[55]
  PIN compiled_identity[56]
    DIRECTION OUTPUT ;
    USE SIGNAL ;
    PORT
      LAYER M4 ;
      RECT 64.716000 60.912000 64.800000 60.936000 ;
    END
  END compiled_identity[56]
  PIN compiled_identity[57]
    DIRECTION OUTPUT ;
    USE SIGNAL ;
    PORT
      LAYER M4 ;
      RECT 64.716000 61.200000 64.800000 61.224000 ;
    END
  END compiled_identity[57]
  PIN compiled_identity[58]
    DIRECTION OUTPUT ;
    USE SIGNAL ;
    PORT
      LAYER M4 ;
      RECT 64.716000 61.536000 64.800000 61.560000 ;
    END
  END compiled_identity[58]
  PIN compiled_generation[0]
    DIRECTION OUTPUT ;
    USE SIGNAL ;
    PORT
      LAYER M4 ;
      RECT 64.716000 61.824000 64.800000 61.848000 ;
    END
  END compiled_generation[0]
  PIN compiled_generation[1]
    DIRECTION OUTPUT ;
    USE SIGNAL ;
    PORT
      LAYER M4 ;
      RECT 64.716000 62.112000 64.800000 62.136000 ;
    END
  END compiled_generation[1]
  PIN fault
    DIRECTION OUTPUT ;
    USE SIGNAL ;
    PORT
      LAYER M4 ;
      RECT 64.716000 62.448000 64.800000 62.472000 ;
    END
  END fault
END qkd_kvn_ctx_ovl_rope
END LIBRARY
